VERSION 5.8 ;
BUSBITCHARS "[]" ;
DIVIDERCHAR "/" ;
UNITS
    DATABASE MICRONS 1000 ;
END UNITS

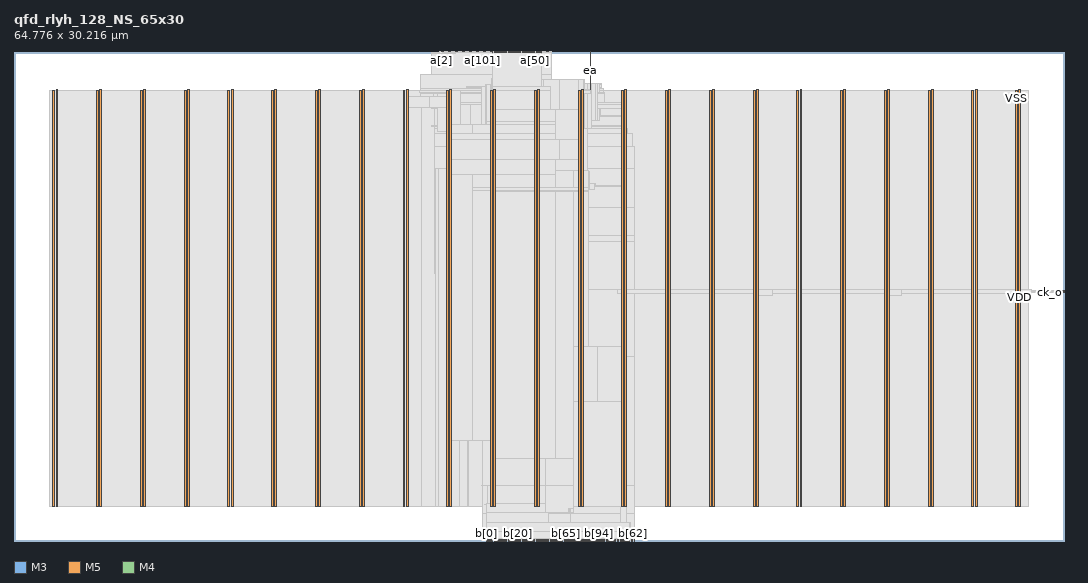
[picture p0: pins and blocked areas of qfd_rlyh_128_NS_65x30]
MACRO qfd_rlyh_128_NS_65x30
  FOREIGN qfd_rlyh_128_NS_65x30 0 0 ;
  CLASS BLOCK ;
  SIZE 64.776 BY 30.216 ;
  PIN a[0]
    DIRECTION INPUT ;
    USE SIGNAL ;
    PORT
      LAYER M3 ;
        RECT  26.244 30.179 26.262 30.216 ;
    END
  END a[0]
  PIN a[100]
    DIRECTION INPUT ;
    USE SIGNAL ;
    PORT
      LAYER M3 ;
        RECT  28.836 30.179 28.854 30.216 ;
    END
  END a[100]
  PIN a[101]
    DIRECTION INPUT ;
    USE SIGNAL ;
    PORT
      LAYER M3 ;
        RECT  28.908 30.179 28.926 30.216 ;
    END
  END a[101]
  PIN a[102]
    DIRECTION INPUT ;
    USE SIGNAL ;
    PORT
      LAYER M3 ;
        RECT  28.98 30.179 28.998 30.216 ;
    END
  END a[102]
  PIN a[103]
    DIRECTION INPUT ;
    USE SIGNAL ;
    PORT
      LAYER M3 ;
        RECT  29.052 30.179 29.07 30.216 ;
    END
  END a[103]
  PIN a[104]
    DIRECTION INPUT ;
    USE SIGNAL ;
    PORT
      LAYER M3 ;
        RECT  29.124 30.179 29.142 30.216 ;
    END
  END a[104]
  PIN a[105]
    DIRECTION INPUT ;
    USE SIGNAL ;
    PORT
      LAYER M3 ;
        RECT  29.196 30.179 29.214 30.216 ;
    END
  END a[105]
  PIN a[106]
    DIRECTION INPUT ;
    USE SIGNAL ;
    PORT
      LAYER M3 ;
        RECT  29.268 30.179 29.286 30.216 ;
    END
  END a[106]
  PIN a[107]
    DIRECTION INPUT ;
    USE SIGNAL ;
    PORT
      LAYER M3 ;
        RECT  29.34 30.179 29.358 30.216 ;
    END
  END a[107]
  PIN a[108]
    DIRECTION INPUT ;
    USE SIGNAL ;
    PORT
      LAYER M3 ;
        RECT  29.412 30.179 29.43 30.216 ;
    END
  END a[108]
  PIN a[109]
    DIRECTION INPUT ;
    USE SIGNAL ;
    PORT
      LAYER M3 ;
        RECT  29.484 30.179 29.502 30.216 ;
    END
  END a[109]
  PIN a[10]
    DIRECTION INPUT ;
    USE SIGNAL ;
    PORT
      LAYER M3 ;
        RECT  26.964 30.179 26.982 30.216 ;
    END
  END a[10]
  PIN a[110]
    DIRECTION INPUT ;
    USE SIGNAL ;
    PORT
      LAYER M3 ;
        RECT  29.556 30.179 29.574 30.216 ;
    END
  END a[110]
  PIN a[111]
    DIRECTION INPUT ;
    USE SIGNAL ;
    PORT
      LAYER M3 ;
        RECT  29.628 30.179 29.646 30.216 ;
    END
  END a[111]
  PIN a[112]
    DIRECTION INPUT ;
    USE SIGNAL ;
    PORT
      LAYER M3 ;
        RECT  29.7 30.179 29.718 30.216 ;
    END
  END a[112]
  PIN a[113]
    DIRECTION INPUT ;
    USE SIGNAL ;
    PORT
      LAYER M3 ;
        RECT  29.772 30.179 29.79 30.216 ;
    END
  END a[113]
  PIN a[114]
    DIRECTION INPUT ;
    USE SIGNAL ;
    PORT
      LAYER M3 ;
        RECT  29.844 30.179 29.862 30.216 ;
    END
  END a[114]
  PIN a[115]
    DIRECTION INPUT ;
    USE SIGNAL ;
    PORT
      LAYER M3 ;
        RECT  29.916 30.179 29.934 30.216 ;
    END
  END a[115]
  PIN a[116]
    DIRECTION INPUT ;
    USE SIGNAL ;
    PORT
      LAYER M3 ;
        RECT  29.988 30.179 30.006 30.216 ;
    END
  END a[116]
  PIN a[117]
    DIRECTION INPUT ;
    USE SIGNAL ;
    PORT
      LAYER M3 ;
        RECT  30.06 30.179 30.078 30.216 ;
    END
  END a[117]
  PIN a[118]
    DIRECTION INPUT ;
    USE SIGNAL ;
    PORT
      LAYER M3 ;
        RECT  30.132 30.179 30.15 30.216 ;
    END
  END a[118]
  PIN a[119]
    DIRECTION INPUT ;
    USE SIGNAL ;
    PORT
      LAYER M3 ;
        RECT  30.204 30.179 30.222 30.216 ;
    END
  END a[119]
  PIN a[11]
    DIRECTION INPUT ;
    USE SIGNAL ;
    PORT
      LAYER M3 ;
        RECT  27.036 30.179 27.054 30.216 ;
    END
  END a[11]
  PIN a[120]
    DIRECTION INPUT ;
    USE SIGNAL ;
    PORT
      LAYER M3 ;
        RECT  30.276 30.179 30.294 30.216 ;
    END
  END a[120]
  PIN a[121]
    DIRECTION INPUT ;
    USE SIGNAL ;
    PORT
      LAYER M3 ;
        RECT  30.348 30.179 30.366 30.216 ;
    END
  END a[121]
  PIN a[122]
    DIRECTION INPUT ;
    USE SIGNAL ;
    PORT
      LAYER M3 ;
        RECT  30.42 30.179 30.438 30.216 ;
    END
  END a[122]
  PIN a[123]
    DIRECTION INPUT ;
    USE SIGNAL ;
    PORT
      LAYER M3 ;
        RECT  30.492 30.179 30.51 30.216 ;
    END
  END a[123]
  PIN a[124]
    DIRECTION INPUT ;
    USE SIGNAL ;
    PORT
      LAYER M3 ;
        RECT  30.564 30.179 30.582 30.216 ;
    END
  END a[124]
  PIN a[125]
    DIRECTION INPUT ;
    USE SIGNAL ;
    PORT
      LAYER M3 ;
        RECT  30.636 30.179 30.654 30.216 ;
    END
  END a[125]
  PIN a[126]
    DIRECTION INPUT ;
    USE SIGNAL ;
    PORT
      LAYER M3 ;
        RECT  30.708 30.179 30.726 30.216 ;
    END
  END a[126]
  PIN a[127]
    DIRECTION INPUT ;
    USE SIGNAL ;
    PORT
      LAYER M3 ;
        RECT  30.78 30.179 30.798 30.216 ;
    END
  END a[127]
  PIN a[12]
    DIRECTION INPUT ;
    USE SIGNAL ;
    PORT
      LAYER M3 ;
        RECT  27.108 30.179 27.126 30.216 ;
    END
  END a[12]
  PIN a[13]
    DIRECTION INPUT ;
    USE SIGNAL ;
    PORT
      LAYER M3 ;
        RECT  27.18 30.179 27.198 30.216 ;
    END
  END a[13]
  PIN a[14]
    DIRECTION INPUT ;
    USE SIGNAL ;
    PORT
      LAYER M3 ;
        RECT  27.252 30.179 27.27 30.216 ;
    END
  END a[14]
  PIN a[15]
    DIRECTION INPUT ;
    USE SIGNAL ;
    PORT
      LAYER M3 ;
        RECT  27.324 30.179 27.342 30.216 ;
    END
  END a[15]
  PIN a[16]
    DIRECTION INPUT ;
    USE SIGNAL ;
    PORT
      LAYER M3 ;
        RECT  27.396 30.179 27.414 30.216 ;
    END
  END a[16]
  PIN a[17]
    DIRECTION INPUT ;
    USE SIGNAL ;
    PORT
      LAYER M3 ;
        RECT  27.468 30.179 27.486 30.216 ;
    END
  END a[17]
  PIN a[18]
    DIRECTION INPUT ;
    USE SIGNAL ;
    PORT
      LAYER M3 ;
        RECT  27.54 30.179 27.558 30.216 ;
    END
  END a[18]
  PIN a[19]
    DIRECTION INPUT ;
    USE SIGNAL ;
    PORT
      LAYER M3 ;
        RECT  27.612 30.179 27.63 30.216 ;
    END
  END a[19]
  PIN a[1]
    DIRECTION INPUT ;
    USE SIGNAL ;
    PORT
      LAYER M3 ;
        RECT  26.316 30.179 26.334 30.216 ;
    END
  END a[1]
  PIN a[20]
    DIRECTION INPUT ;
    USE SIGNAL ;
    PORT
      LAYER M3 ;
        RECT  27.684 30.179 27.702 30.216 ;
    END
  END a[20]
  PIN a[21]
    DIRECTION INPUT ;
    USE SIGNAL ;
    PORT
      LAYER M3 ;
        RECT  27.756 30.179 27.774 30.216 ;
    END
  END a[21]
  PIN a[22]
    DIRECTION INPUT ;
    USE SIGNAL ;
    PORT
      LAYER M3 ;
        RECT  27.828 30.179 27.846 30.216 ;
    END
  END a[22]
  PIN a[23]
    DIRECTION INPUT ;
    USE SIGNAL ;
    PORT
      LAYER M3 ;
        RECT  27.9 30.179 27.918 30.216 ;
    END
  END a[23]
  PIN a[24]
    DIRECTION INPUT ;
    USE SIGNAL ;
    PORT
      LAYER M3 ;
        RECT  27.972 30.179 27.99 30.216 ;
    END
  END a[24]
  PIN a[25]
    DIRECTION INPUT ;
    USE SIGNAL ;
    PORT
      LAYER M3 ;
        RECT  28.044 30.179 28.062 30.216 ;
    END
  END a[25]
  PIN a[26]
    DIRECTION INPUT ;
    USE SIGNAL ;
    PORT
      LAYER M3 ;
        RECT  28.116 30.179 28.134 30.216 ;
    END
  END a[26]
  PIN a[27]
    DIRECTION INPUT ;
    USE SIGNAL ;
    PORT
      LAYER M3 ;
        RECT  28.188 30.179 28.206 30.216 ;
    END
  END a[27]
  PIN a[28]
    DIRECTION INPUT ;
    USE SIGNAL ;
    PORT
      LAYER M3 ;
        RECT  28.26 30.179 28.278 30.216 ;
    END
  END a[28]
  PIN a[29]
    DIRECTION INPUT ;
    USE SIGNAL ;
    PORT
      LAYER M3 ;
        RECT  28.332 30.179 28.35 30.216 ;
    END
  END a[29]
  PIN a[2]
    DIRECTION INPUT ;
    USE SIGNAL ;
    PORT
      LAYER M3 ;
        RECT  26.388 30.179 26.406 30.216 ;
    END
  END a[2]
  PIN a[30]
    DIRECTION INPUT ;
    USE SIGNAL ;
    PORT
      LAYER M3 ;
        RECT  28.404 30.179 28.422 30.216 ;
    END
  END a[30]
  PIN a[31]
    DIRECTION INPUT ;
    USE SIGNAL ;
    PORT
      LAYER M3 ;
        RECT  28.476 30.179 28.494 30.216 ;
    END
  END a[31]
  PIN a[32]
    DIRECTION INPUT ;
    USE SIGNAL ;
    PORT
      LAYER M3 ;
        RECT  30.852 30.179 30.87 30.216 ;
    END
  END a[32]
  PIN a[33]
    DIRECTION INPUT ;
    USE SIGNAL ;
    PORT
      LAYER M3 ;
        RECT  30.924 30.179 30.942 30.216 ;
    END
  END a[33]
  PIN a[34]
    DIRECTION INPUT ;
    USE SIGNAL ;
    PORT
      LAYER M3 ;
        RECT  30.996 30.179 31.014 30.216 ;
    END
  END a[34]
  PIN a[35]
    DIRECTION INPUT ;
    USE SIGNAL ;
    PORT
      LAYER M3 ;
        RECT  31.068 30.179 31.086 30.216 ;
    END
  END a[35]
  PIN a[36]
    DIRECTION INPUT ;
    USE SIGNAL ;
    PORT
      LAYER M3 ;
        RECT  31.14 30.179 31.158 30.216 ;
    END
  END a[36]
  PIN a[37]
    DIRECTION INPUT ;
    USE SIGNAL ;
    PORT
      LAYER M3 ;
        RECT  31.212 30.179 31.23 30.216 ;
    END
  END a[37]
  PIN a[38]
    DIRECTION INPUT ;
    USE SIGNAL ;
    PORT
      LAYER M3 ;
        RECT  31.284 30.179 31.302 30.216 ;
    END
  END a[38]
  PIN a[39]
    DIRECTION INPUT ;
    USE SIGNAL ;
    PORT
      LAYER M3 ;
        RECT  31.356 30.179 31.374 30.216 ;
    END
  END a[39]
  PIN a[3]
    DIRECTION INPUT ;
    USE SIGNAL ;
    PORT
      LAYER M3 ;
        RECT  26.46 30.179 26.478 30.216 ;
    END
  END a[3]
  PIN a[40]
    DIRECTION INPUT ;
    USE SIGNAL ;
    PORT
      LAYER M3 ;
        RECT  31.428 30.179 31.446 30.216 ;
    END
  END a[40]
  PIN a[41]
    DIRECTION INPUT ;
    USE SIGNAL ;
    PORT
      LAYER M3 ;
        RECT  31.5 30.179 31.518 30.216 ;
    END
  END a[41]
  PIN a[42]
    DIRECTION INPUT ;
    USE SIGNAL ;
    PORT
      LAYER M3 ;
        RECT  31.572 30.179 31.59 30.216 ;
    END
  END a[42]
  PIN a[43]
    DIRECTION INPUT ;
    USE SIGNAL ;
    PORT
      LAYER M3 ;
        RECT  31.644 30.179 31.662 30.216 ;
    END
  END a[43]
  PIN a[44]
    DIRECTION INPUT ;
    USE SIGNAL ;
    PORT
      LAYER M3 ;
        RECT  31.716 30.179 31.734 30.216 ;
    END
  END a[44]
  PIN a[45]
    DIRECTION INPUT ;
    USE SIGNAL ;
    PORT
      LAYER M3 ;
        RECT  31.788 30.179 31.806 30.216 ;
    END
  END a[45]
  PIN a[46]
    DIRECTION INPUT ;
    USE SIGNAL ;
    PORT
      LAYER M3 ;
        RECT  31.86 30.179 31.878 30.216 ;
    END
  END a[46]
  PIN a[47]
    DIRECTION INPUT ;
    USE SIGNAL ;
    PORT
      LAYER M3 ;
        RECT  31.932 30.179 31.95 30.216 ;
    END
  END a[47]
  PIN a[48]
    DIRECTION INPUT ;
    USE SIGNAL ;
    PORT
      LAYER M3 ;
        RECT  32.004 30.179 32.022 30.216 ;
    END
  END a[48]
  PIN a[49]
    DIRECTION INPUT ;
    USE SIGNAL ;
    PORT
      LAYER M3 ;
        RECT  32.076 30.179 32.094 30.216 ;
    END
  END a[49]
  PIN a[4]
    DIRECTION INPUT ;
    USE SIGNAL ;
    PORT
      LAYER M3 ;
        RECT  26.532 30.179 26.55 30.216 ;
    END
  END a[4]
  PIN a[50]
    DIRECTION INPUT ;
    USE SIGNAL ;
    PORT
      LAYER M3 ;
        RECT  32.148 30.179 32.166 30.216 ;
    END
  END a[50]
  PIN a[51]
    DIRECTION INPUT ;
    USE SIGNAL ;
    PORT
      LAYER M3 ;
        RECT  32.22 30.179 32.238 30.216 ;
    END
  END a[51]
  PIN a[52]
    DIRECTION INPUT ;
    USE SIGNAL ;
    PORT
      LAYER M3 ;
        RECT  32.292 30.179 32.31 30.216 ;
    END
  END a[52]
  PIN a[53]
    DIRECTION INPUT ;
    USE SIGNAL ;
    PORT
      LAYER M3 ;
        RECT  32.364 30.179 32.382 30.216 ;
    END
  END a[53]
  PIN a[54]
    DIRECTION INPUT ;
    USE SIGNAL ;
    PORT
      LAYER M3 ;
        RECT  32.436 30.179 32.454 30.216 ;
    END
  END a[54]
  PIN a[55]
    DIRECTION INPUT ;
    USE SIGNAL ;
    PORT
      LAYER M3 ;
        RECT  32.508 30.179 32.526 30.216 ;
    END
  END a[55]
  PIN a[56]
    DIRECTION INPUT ;
    USE SIGNAL ;
    PORT
      LAYER M3 ;
        RECT  32.58 30.179 32.598 30.216 ;
    END
  END a[56]
  PIN a[57]
    DIRECTION INPUT ;
    USE SIGNAL ;
    PORT
      LAYER M3 ;
        RECT  32.652 30.179 32.67 30.216 ;
    END
  END a[57]
  PIN a[58]
    DIRECTION INPUT ;
    USE SIGNAL ;
    PORT
      LAYER M3 ;
        RECT  32.724 30.179 32.742 30.216 ;
    END
  END a[58]
  PIN a[59]
    DIRECTION INPUT ;
    USE SIGNAL ;
    PORT
      LAYER M3 ;
        RECT  32.796 30.179 32.814 30.216 ;
    END
  END a[59]
  PIN a[5]
    DIRECTION INPUT ;
    USE SIGNAL ;
    PORT
      LAYER M3 ;
        RECT  26.604 30.179 26.622 30.216 ;
    END
  END a[5]
  PIN a[60]
    DIRECTION INPUT ;
    USE SIGNAL ;
    PORT
      LAYER M3 ;
        RECT  32.868 30.179 32.886 30.216 ;
    END
  END a[60]
  PIN a[61]
    DIRECTION INPUT ;
    USE SIGNAL ;
    PORT
      LAYER M3 ;
        RECT  32.94 30.179 32.958 30.216 ;
    END
  END a[61]
  PIN a[62]
    DIRECTION INPUT ;
    USE SIGNAL ;
    PORT
      LAYER M3 ;
        RECT  33.012 30.179 33.03 30.216 ;
    END
  END a[62]
  PIN a[63]
    DIRECTION INPUT ;
    USE SIGNAL ;
    PORT
      LAYER M3 ;
        RECT  33.084 30.179 33.102 30.216 ;
    END
  END a[63]
  PIN a[64]
    DIRECTION INPUT ;
    USE SIGNAL ;
    PORT
      LAYER M5 ;
        RECT  29.52 30.132 29.544 30.216 ;
    END
  END a[64]
  PIN a[65]
    DIRECTION INPUT ;
    USE SIGNAL ;
    PORT
      LAYER M5 ;
        RECT  29.616 30.132 29.64 30.216 ;
    END
  END a[65]
  PIN a[66]
    DIRECTION INPUT ;
    USE SIGNAL ;
    PORT
      LAYER M5 ;
        RECT  29.712 30.132 29.736 30.216 ;
    END
  END a[66]
  PIN a[67]
    DIRECTION INPUT ;
    USE SIGNAL ;
    PORT
      LAYER M5 ;
        RECT  29.808 30.132 29.832 30.216 ;
    END
  END a[67]
  PIN a[68]
    DIRECTION INPUT ;
    USE SIGNAL ;
    PORT
      LAYER M5 ;
        RECT  29.904 30.132 29.928 30.216 ;
    END
  END a[68]
  PIN a[69]
    DIRECTION INPUT ;
    USE SIGNAL ;
    PORT
      LAYER M5 ;
        RECT  30 30.132 30.024 30.216 ;
    END
  END a[69]
  PIN a[6]
    DIRECTION INPUT ;
    USE SIGNAL ;
    PORT
      LAYER M3 ;
        RECT  26.676 30.179 26.694 30.216 ;
    END
  END a[6]
  PIN a[70]
    DIRECTION INPUT ;
    USE SIGNAL ;
    PORT
      LAYER M5 ;
        RECT  30.096 30.132 30.12 30.216 ;
    END
  END a[70]
  PIN a[71]
    DIRECTION INPUT ;
    USE SIGNAL ;
    PORT
      LAYER M5 ;
        RECT  30.192 30.132 30.216 30.216 ;
    END
  END a[71]
  PIN a[72]
    DIRECTION INPUT ;
    USE SIGNAL ;
    PORT
      LAYER M5 ;
        RECT  30.288 30.132 30.312 30.216 ;
    END
  END a[72]
  PIN a[73]
    DIRECTION INPUT ;
    USE SIGNAL ;
    PORT
      LAYER M5 ;
        RECT  30.384 30.132 30.408 30.216 ;
    END
  END a[73]
  PIN a[74]
    DIRECTION INPUT ;
    USE SIGNAL ;
    PORT
      LAYER M5 ;
        RECT  30.48 30.132 30.504 30.216 ;
    END
  END a[74]
  PIN a[75]
    DIRECTION INPUT ;
    USE SIGNAL ;
    PORT
      LAYER M5 ;
        RECT  30.576 30.132 30.6 30.216 ;
    END
  END a[75]
  PIN a[76]
    DIRECTION INPUT ;
    USE SIGNAL ;
    PORT
      LAYER M5 ;
        RECT  30.672 30.132 30.696 30.216 ;
    END
  END a[76]
  PIN a[77]
    DIRECTION INPUT ;
    USE SIGNAL ;
    PORT
      LAYER M5 ;
        RECT  30.768 30.132 30.792 30.216 ;
    END
  END a[77]
  PIN a[78]
    DIRECTION INPUT ;
    USE SIGNAL ;
    PORT
      LAYER M5 ;
        RECT  30.864 30.132 30.888 30.216 ;
    END
  END a[78]
  PIN a[79]
    DIRECTION INPUT ;
    USE SIGNAL ;
    PORT
      LAYER M5 ;
        RECT  30.96 30.132 30.984 30.216 ;
    END
  END a[79]
  PIN a[7]
    DIRECTION INPUT ;
    USE SIGNAL ;
    PORT
      LAYER M3 ;
        RECT  26.748 30.179 26.766 30.216 ;
    END
  END a[7]
  PIN a[80]
    DIRECTION INPUT ;
    USE SIGNAL ;
    PORT
      LAYER M5 ;
        RECT  31.056 30.132 31.08 30.216 ;
    END
  END a[80]
  PIN a[81]
    DIRECTION INPUT ;
    USE SIGNAL ;
    PORT
      LAYER M5 ;
        RECT  31.152 30.132 31.176 30.216 ;
    END
  END a[81]
  PIN a[82]
    DIRECTION INPUT ;
    USE SIGNAL ;
    PORT
      LAYER M5 ;
        RECT  31.248 30.132 31.272 30.216 ;
    END
  END a[82]
  PIN a[83]
    DIRECTION INPUT ;
    USE SIGNAL ;
    PORT
      LAYER M5 ;
        RECT  31.344 30.132 31.368 30.216 ;
    END
  END a[83]
  PIN a[84]
    DIRECTION INPUT ;
    USE SIGNAL ;
    PORT
      LAYER M5 ;
        RECT  31.44 30.132 31.464 30.216 ;
    END
  END a[84]
  PIN a[85]
    DIRECTION INPUT ;
    USE SIGNAL ;
    PORT
      LAYER M5 ;
        RECT  31.536 30.132 31.56 30.216 ;
    END
  END a[85]
  PIN a[86]
    DIRECTION INPUT ;
    USE SIGNAL ;
    PORT
      LAYER M5 ;
        RECT  31.632 30.132 31.656 30.216 ;
    END
  END a[86]
  PIN a[87]
    DIRECTION INPUT ;
    USE SIGNAL ;
    PORT
      LAYER M5 ;
        RECT  31.728 30.132 31.752 30.216 ;
    END
  END a[87]
  PIN a[88]
    DIRECTION INPUT ;
    USE SIGNAL ;
    PORT
      LAYER M5 ;
        RECT  31.824 30.132 31.848 30.216 ;
    END
  END a[88]
  PIN a[89]
    DIRECTION INPUT ;
    USE SIGNAL ;
    PORT
      LAYER M5 ;
        RECT  31.92 30.132 31.944 30.216 ;
    END
  END a[89]
  PIN a[8]
    DIRECTION INPUT ;
    USE SIGNAL ;
    PORT
      LAYER M3 ;
        RECT  26.82 30.179 26.838 30.216 ;
    END
  END a[8]
  PIN a[90]
    DIRECTION INPUT ;
    USE SIGNAL ;
    PORT
      LAYER M5 ;
        RECT  32.016 30.132 32.04 30.216 ;
    END
  END a[90]
  PIN a[91]
    DIRECTION INPUT ;
    USE SIGNAL ;
    PORT
      LAYER M5 ;
        RECT  32.112 30.132 32.136 30.216 ;
    END
  END a[91]
  PIN a[92]
    DIRECTION INPUT ;
    USE SIGNAL ;
    PORT
      LAYER M5 ;
        RECT  32.208 30.132 32.232 30.216 ;
    END
  END a[92]
  PIN a[93]
    DIRECTION INPUT ;
    USE SIGNAL ;
    PORT
      LAYER M5 ;
        RECT  32.304 30.132 32.328 30.216 ;
    END
  END a[93]
  PIN a[94]
    DIRECTION INPUT ;
    USE SIGNAL ;
    PORT
      LAYER M5 ;
        RECT  32.4 30.132 32.424 30.216 ;
    END
  END a[94]
  PIN a[95]
    DIRECTION INPUT ;
    USE SIGNAL ;
    PORT
      LAYER M5 ;
        RECT  32.496 30.132 32.52 30.216 ;
    END
  END a[95]
  PIN a[96]
    DIRECTION INPUT ;
    USE SIGNAL ;
    PORT
      LAYER M3 ;
        RECT  28.548 30.179 28.566 30.216 ;
    END
  END a[96]
  PIN a[97]
    DIRECTION INPUT ;
    USE SIGNAL ;
    PORT
      LAYER M3 ;
        RECT  28.62 30.179 28.638 30.216 ;
    END
  END a[97]
  PIN a[98]
    DIRECTION INPUT ;
    USE SIGNAL ;
    PORT
      LAYER M3 ;
        RECT  28.692 30.179 28.71 30.216 ;
    END
  END a[98]
  PIN a[99]
    DIRECTION INPUT ;
    USE SIGNAL ;
    PORT
      LAYER M3 ;
        RECT  28.764 30.179 28.782 30.216 ;
    END
  END a[99]
  PIN a[9]
    DIRECTION INPUT ;
    USE SIGNAL ;
    PORT
      LAYER M3 ;
        RECT  26.892 30.179 26.91 30.216 ;
    END
  END a[9]
  PIN b[0]
    DIRECTION OUTPUT ;
    USE SIGNAL ;
    PORT
      LAYER M5 ;
        RECT  29.136 0 29.16 0.084 ;
    END
  END b[0]
  PIN b[100]
    DIRECTION OUTPUT ;
    USE SIGNAL ;
    PORT
      LAYER M5 ;
        RECT  32.592 0 32.616 0.084 ;
    END
  END b[100]
  PIN b[101]
    DIRECTION OUTPUT ;
    USE SIGNAL ;
    PORT
      LAYER M5 ;
        RECT  32.688 0 32.712 0.084 ;
    END
  END b[101]
  PIN b[102]
    DIRECTION OUTPUT ;
    USE SIGNAL ;
    PORT
      LAYER M5 ;
        RECT  32.784 0 32.808 0.084 ;
    END
  END b[102]
  PIN b[103]
    DIRECTION OUTPUT ;
    USE SIGNAL ;
    PORT
      LAYER M5 ;
        RECT  32.88 0 32.904 0.084 ;
    END
  END b[103]
  PIN b[104]
    DIRECTION OUTPUT ;
    USE SIGNAL ;
    PORT
      LAYER M5 ;
        RECT  32.976 0 33 0.084 ;
    END
  END b[104]
  PIN b[105]
    DIRECTION OUTPUT ;
    USE SIGNAL ;
    PORT
      LAYER M5 ;
        RECT  33.072 0 33.096 0.084 ;
    END
  END b[105]
  PIN b[106]
    DIRECTION OUTPUT ;
    USE SIGNAL ;
    PORT
      LAYER M5 ;
        RECT  33.168 0 33.192 0.084 ;
    END
  END b[106]
  PIN b[107]
    DIRECTION OUTPUT ;
    USE SIGNAL ;
    PORT
      LAYER M5 ;
        RECT  33.264 0 33.288 0.084 ;
    END
  END b[107]
  PIN b[108]
    DIRECTION OUTPUT ;
    USE SIGNAL ;
    PORT
      LAYER M5 ;
        RECT  33.36 0 33.384 0.084 ;
    END
  END b[108]
  PIN b[109]
    DIRECTION OUTPUT ;
    USE SIGNAL ;
    PORT
      LAYER M5 ;
        RECT  33.456 0 33.48 0.084 ;
    END
  END b[109]
  PIN b[10]
    DIRECTION OUTPUT ;
    USE SIGNAL ;
    PORT
      LAYER M5 ;
        RECT  30.096 0 30.12 0.084 ;
    END
  END b[10]
  PIN b[110]
    DIRECTION OUTPUT ;
    USE SIGNAL ;
    PORT
      LAYER M5 ;
        RECT  33.552 0 33.576 0.084 ;
    END
  END b[110]
  PIN b[111]
    DIRECTION OUTPUT ;
    USE SIGNAL ;
    PORT
      LAYER M5 ;
        RECT  33.648 0 33.672 0.084 ;
    END
  END b[111]
  PIN b[112]
    DIRECTION OUTPUT ;
    USE SIGNAL ;
    PORT
      LAYER M5 ;
        RECT  33.744 0 33.768 0.084 ;
    END
  END b[112]
  PIN b[113]
    DIRECTION OUTPUT ;
    USE SIGNAL ;
    PORT
      LAYER M5 ;
        RECT  33.84 0 33.864 0.084 ;
    END
  END b[113]
  PIN b[114]
    DIRECTION OUTPUT ;
    USE SIGNAL ;
    PORT
      LAYER M5 ;
        RECT  33.936 0 33.96 0.084 ;
    END
  END b[114]
  PIN b[115]
    DIRECTION OUTPUT ;
    USE SIGNAL ;
    PORT
      LAYER M5 ;
        RECT  34.032 0 34.056 0.084 ;
    END
  END b[115]
  PIN b[116]
    DIRECTION OUTPUT ;
    USE SIGNAL ;
    PORT
      LAYER M5 ;
        RECT  34.128 0 34.152 0.084 ;
    END
  END b[116]
  PIN b[117]
    DIRECTION OUTPUT ;
    USE SIGNAL ;
    PORT
      LAYER M5 ;
        RECT  34.224 0 34.248 0.084 ;
    END
  END b[117]
  PIN b[118]
    DIRECTION OUTPUT ;
    USE SIGNAL ;
    PORT
      LAYER M5 ;
        RECT  34.32 0 34.344 0.084 ;
    END
  END b[118]
  PIN b[119]
    DIRECTION OUTPUT ;
    USE SIGNAL ;
    PORT
      LAYER M5 ;
        RECT  34.416 0 34.44 0.084 ;
    END
  END b[119]
  PIN b[11]
    DIRECTION OUTPUT ;
    USE SIGNAL ;
    PORT
      LAYER M5 ;
        RECT  30.192 0 30.216 0.084 ;
    END
  END b[11]
  PIN b[120]
    DIRECTION OUTPUT ;
    USE SIGNAL ;
    PORT
      LAYER M5 ;
        RECT  34.512 0 34.536 0.084 ;
    END
  END b[120]
  PIN b[121]
    DIRECTION OUTPUT ;
    USE SIGNAL ;
    PORT
      LAYER M5 ;
        RECT  34.608 0 34.632 0.084 ;
    END
  END b[121]
  PIN b[122]
    DIRECTION OUTPUT ;
    USE SIGNAL ;
    PORT
      LAYER M5 ;
        RECT  34.704 0 34.728 0.084 ;
    END
  END b[122]
  PIN b[123]
    DIRECTION OUTPUT ;
    USE SIGNAL ;
    PORT
      LAYER M5 ;
        RECT  34.8 0 34.824 0.084 ;
    END
  END b[123]
  PIN b[124]
    DIRECTION OUTPUT ;
    USE SIGNAL ;
    PORT
      LAYER M5 ;
        RECT  34.896 0 34.92 0.084 ;
    END
  END b[124]
  PIN b[125]
    DIRECTION OUTPUT ;
    USE SIGNAL ;
    PORT
      LAYER M5 ;
        RECT  34.992 0 35.016 0.084 ;
    END
  END b[125]
  PIN b[126]
    DIRECTION OUTPUT ;
    USE SIGNAL ;
    PORT
      LAYER M5 ;
        RECT  35.088 0 35.112 0.084 ;
    END
  END b[126]
  PIN b[127]
    DIRECTION OUTPUT ;
    USE SIGNAL ;
    PORT
      LAYER M5 ;
        RECT  35.184 0 35.208 0.084 ;
    END
  END b[127]
  PIN b[12]
    DIRECTION OUTPUT ;
    USE SIGNAL ;
    PORT
      LAYER M5 ;
        RECT  30.288 0 30.312 0.084 ;
    END
  END b[12]
  PIN b[13]
    DIRECTION OUTPUT ;
    USE SIGNAL ;
    PORT
      LAYER M5 ;
        RECT  30.384 0 30.408 0.084 ;
    END
  END b[13]
  PIN b[14]
    DIRECTION OUTPUT ;
    USE SIGNAL ;
    PORT
      LAYER M5 ;
        RECT  30.48 0 30.504 0.084 ;
    END
  END b[14]
  PIN b[15]
    DIRECTION OUTPUT ;
    USE SIGNAL ;
    PORT
      LAYER M5 ;
        RECT  30.576 0 30.6 0.084 ;
    END
  END b[15]
  PIN b[16]
    DIRECTION OUTPUT ;
    USE SIGNAL ;
    PORT
      LAYER M5 ;
        RECT  30.672 0 30.696 0.084 ;
    END
  END b[16]
  PIN b[17]
    DIRECTION OUTPUT ;
    USE SIGNAL ;
    PORT
      LAYER M5 ;
        RECT  30.768 0 30.792 0.084 ;
    END
  END b[17]
  PIN b[18]
    DIRECTION OUTPUT ;
    USE SIGNAL ;
    PORT
      LAYER M5 ;
        RECT  30.864 0 30.888 0.084 ;
    END
  END b[18]
  PIN b[19]
    DIRECTION OUTPUT ;
    USE SIGNAL ;
    PORT
      LAYER M5 ;
        RECT  30.96 0 30.984 0.084 ;
    END
  END b[19]
  PIN b[1]
    DIRECTION OUTPUT ;
    USE SIGNAL ;
    PORT
      LAYER M5 ;
        RECT  29.232 0 29.256 0.084 ;
    END
  END b[1]
  PIN b[20]
    DIRECTION OUTPUT ;
    USE SIGNAL ;
    PORT
      LAYER M5 ;
        RECT  31.056 0 31.08 0.084 ;
    END
  END b[20]
  PIN b[21]
    DIRECTION OUTPUT ;
    USE SIGNAL ;
    PORT
      LAYER M5 ;
        RECT  31.152 0 31.176 0.084 ;
    END
  END b[21]
  PIN b[22]
    DIRECTION OUTPUT ;
    USE SIGNAL ;
    PORT
      LAYER M5 ;
        RECT  31.248 0 31.272 0.084 ;
    END
  END b[22]
  PIN b[23]
    DIRECTION OUTPUT ;
    USE SIGNAL ;
    PORT
      LAYER M5 ;
        RECT  31.344 0 31.368 0.084 ;
    END
  END b[23]
  PIN b[24]
    DIRECTION OUTPUT ;
    USE SIGNAL ;
    PORT
      LAYER M5 ;
        RECT  31.44 0 31.464 0.084 ;
    END
  END b[24]
  PIN b[25]
    DIRECTION OUTPUT ;
    USE SIGNAL ;
    PORT
      LAYER M5 ;
        RECT  31.536 0 31.56 0.084 ;
    END
  END b[25]
  PIN b[26]
    DIRECTION OUTPUT ;
    USE SIGNAL ;
    PORT
      LAYER M5 ;
        RECT  31.632 0 31.656 0.084 ;
    END
  END b[26]
  PIN b[27]
    DIRECTION OUTPUT ;
    USE SIGNAL ;
    PORT
      LAYER M5 ;
        RECT  31.728 0 31.752 0.084 ;
    END
  END b[27]
  PIN b[28]
    DIRECTION OUTPUT ;
    USE SIGNAL ;
    PORT
      LAYER M5 ;
        RECT  31.824 0 31.848 0.084 ;
    END
  END b[28]
  PIN b[29]
    DIRECTION OUTPUT ;
    USE SIGNAL ;
    PORT
      LAYER M5 ;
        RECT  31.92 0 31.944 0.084 ;
    END
  END b[29]
  PIN b[2]
    DIRECTION OUTPUT ;
    USE SIGNAL ;
    PORT
      LAYER M5 ;
        RECT  29.328 0 29.352 0.084 ;
    END
  END b[2]
  PIN b[30]
    DIRECTION OUTPUT ;
    USE SIGNAL ;
    PORT
      LAYER M5 ;
        RECT  32.016 0 32.04 0.084 ;
    END
  END b[30]
  PIN b[31]
    DIRECTION OUTPUT ;
    USE SIGNAL ;
    PORT
      LAYER M5 ;
        RECT  32.112 0 32.136 0.084 ;
    END
  END b[31]
  PIN b[32]
    DIRECTION OUTPUT ;
    USE SIGNAL ;
    PORT
      LAYER M5 ;
        RECT  35.28 0 35.304 0.084 ;
    END
  END b[32]
  PIN b[33]
    DIRECTION OUTPUT ;
    USE SIGNAL ;
    PORT
      LAYER M5 ;
        RECT  35.376 0 35.4 0.084 ;
    END
  END b[33]
  PIN b[34]
    DIRECTION OUTPUT ;
    USE SIGNAL ;
    PORT
      LAYER M5 ;
        RECT  35.472 0 35.496 0.084 ;
    END
  END b[34]
  PIN b[35]
    DIRECTION OUTPUT ;
    USE SIGNAL ;
    PORT
      LAYER M5 ;
        RECT  35.568 0 35.592 0.084 ;
    END
  END b[35]
  PIN b[36]
    DIRECTION OUTPUT ;
    USE SIGNAL ;
    PORT
      LAYER M5 ;
        RECT  35.664 0 35.688 0.084 ;
    END
  END b[36]
  PIN b[37]
    DIRECTION OUTPUT ;
    USE SIGNAL ;
    PORT
      LAYER M5 ;
        RECT  35.76 0 35.784 0.084 ;
    END
  END b[37]
  PIN b[38]
    DIRECTION OUTPUT ;
    USE SIGNAL ;
    PORT
      LAYER M5 ;
        RECT  35.856 0 35.88 0.084 ;
    END
  END b[38]
  PIN b[39]
    DIRECTION OUTPUT ;
    USE SIGNAL ;
    PORT
      LAYER M5 ;
        RECT  35.952 0 35.976 0.084 ;
    END
  END b[39]
  PIN b[3]
    DIRECTION OUTPUT ;
    USE SIGNAL ;
    PORT
      LAYER M5 ;
        RECT  29.424 0 29.448 0.084 ;
    END
  END b[3]
  PIN b[40]
    DIRECTION OUTPUT ;
    USE SIGNAL ;
    PORT
      LAYER M5 ;
        RECT  36.048 0 36.072 0.084 ;
    END
  END b[40]
  PIN b[41]
    DIRECTION OUTPUT ;
    USE SIGNAL ;
    PORT
      LAYER M5 ;
        RECT  36.144 0 36.168 0.084 ;
    END
  END b[41]
  PIN b[42]
    DIRECTION OUTPUT ;
    USE SIGNAL ;
    PORT
      LAYER M5 ;
        RECT  36.24 0 36.264 0.084 ;
    END
  END b[42]
  PIN b[43]
    DIRECTION OUTPUT ;
    USE SIGNAL ;
    PORT
      LAYER M5 ;
        RECT  36.336 0 36.36 0.084 ;
    END
  END b[43]
  PIN b[44]
    DIRECTION OUTPUT ;
    USE SIGNAL ;
    PORT
      LAYER M5 ;
        RECT  36.432 0 36.456 0.084 ;
    END
  END b[44]
  PIN b[45]
    DIRECTION OUTPUT ;
    USE SIGNAL ;
    PORT
      LAYER M5 ;
        RECT  36.528 0 36.552 0.084 ;
    END
  END b[45]
  PIN b[46]
    DIRECTION OUTPUT ;
    USE SIGNAL ;
    PORT
      LAYER M5 ;
        RECT  36.624 0 36.648 0.084 ;
    END
  END b[46]
  PIN b[47]
    DIRECTION OUTPUT ;
    USE SIGNAL ;
    PORT
      LAYER M5 ;
        RECT  36.72 0 36.744 0.084 ;
    END
  END b[47]
  PIN b[48]
    DIRECTION OUTPUT ;
    USE SIGNAL ;
    PORT
      LAYER M5 ;
        RECT  36.816 0 36.84 0.084 ;
    END
  END b[48]
  PIN b[49]
    DIRECTION OUTPUT ;
    USE SIGNAL ;
    PORT
      LAYER M5 ;
        RECT  36.912 0 36.936 0.084 ;
    END
  END b[49]
  PIN b[4]
    DIRECTION OUTPUT ;
    USE SIGNAL ;
    PORT
      LAYER M5 ;
        RECT  29.52 0 29.544 0.084 ;
    END
  END b[4]
  PIN b[50]
    DIRECTION OUTPUT ;
    USE SIGNAL ;
    PORT
      LAYER M5 ;
        RECT  37.008 0 37.032 0.084 ;
    END
  END b[50]
  PIN b[51]
    DIRECTION OUTPUT ;
    USE SIGNAL ;
    PORT
      LAYER M5 ;
        RECT  37.104 0 37.128 0.084 ;
    END
  END b[51]
  PIN b[52]
    DIRECTION OUTPUT ;
    USE SIGNAL ;
    PORT
      LAYER M5 ;
        RECT  37.2 0 37.224 0.084 ;
    END
  END b[52]
  PIN b[53]
    DIRECTION OUTPUT ;
    USE SIGNAL ;
    PORT
      LAYER M5 ;
        RECT  37.296 0 37.32 0.084 ;
    END
  END b[53]
  PIN b[54]
    DIRECTION OUTPUT ;
    USE SIGNAL ;
    PORT
      LAYER M5 ;
        RECT  37.392 0 37.416 0.084 ;
    END
  END b[54]
  PIN b[55]
    DIRECTION OUTPUT ;
    USE SIGNAL ;
    PORT
      LAYER M5 ;
        RECT  37.488 0 37.512 0.084 ;
    END
  END b[55]
  PIN b[56]
    DIRECTION OUTPUT ;
    USE SIGNAL ;
    PORT
      LAYER M5 ;
        RECT  37.584 0 37.608 0.084 ;
    END
  END b[56]
  PIN b[57]
    DIRECTION OUTPUT ;
    USE SIGNAL ;
    PORT
      LAYER M5 ;
        RECT  37.68 0 37.704 0.084 ;
    END
  END b[57]
  PIN b[58]
    DIRECTION OUTPUT ;
    USE SIGNAL ;
    PORT
      LAYER M5 ;
        RECT  37.776 0 37.8 0.084 ;
    END
  END b[58]
  PIN b[59]
    DIRECTION OUTPUT ;
    USE SIGNAL ;
    PORT
      LAYER M5 ;
        RECT  37.872 0 37.896 0.084 ;
    END
  END b[59]
  PIN b[5]
    DIRECTION OUTPUT ;
    USE SIGNAL ;
    PORT
      LAYER M5 ;
        RECT  29.616 0 29.64 0.084 ;
    END
  END b[5]
  PIN b[60]
    DIRECTION OUTPUT ;
    USE SIGNAL ;
    PORT
      LAYER M5 ;
        RECT  37.968 0 37.992 0.084 ;
    END
  END b[60]
  PIN b[61]
    DIRECTION OUTPUT ;
    USE SIGNAL ;
    PORT
      LAYER M5 ;
        RECT  38.064 0 38.088 0.084 ;
    END
  END b[61]
  PIN b[62]
    DIRECTION OUTPUT ;
    USE SIGNAL ;
    PORT
      LAYER M5 ;
        RECT  38.16 0 38.184 0.084 ;
    END
  END b[62]
  PIN b[63]
    DIRECTION OUTPUT ;
    USE SIGNAL ;
    PORT
      LAYER M5 ;
        RECT  38.256 0 38.28 0.084 ;
    END
  END b[63]
  PIN b[64]
    DIRECTION OUTPUT ;
    USE SIGNAL ;
    PORT
      LAYER M3 ;
        RECT  33.948 0 33.966 0.037 ;
    END
  END b[64]
  PIN b[65]
    DIRECTION OUTPUT ;
    USE SIGNAL ;
    PORT
      LAYER M3 ;
        RECT  34.02 0 34.038 0.037 ;
    END
  END b[65]
  PIN b[66]
    DIRECTION OUTPUT ;
    USE SIGNAL ;
    PORT
      LAYER M3 ;
        RECT  34.092 0 34.11 0.037 ;
    END
  END b[66]
  PIN b[67]
    DIRECTION OUTPUT ;
    USE SIGNAL ;
    PORT
      LAYER M3 ;
        RECT  34.164 0 34.182 0.037 ;
    END
  END b[67]
  PIN b[68]
    DIRECTION OUTPUT ;
    USE SIGNAL ;
    PORT
      LAYER M3 ;
        RECT  34.236 0 34.254 0.037 ;
    END
  END b[68]
  PIN b[69]
    DIRECTION OUTPUT ;
    USE SIGNAL ;
    PORT
      LAYER M3 ;
        RECT  34.308 0 34.326 0.037 ;
    END
  END b[69]
  PIN b[6]
    DIRECTION OUTPUT ;
    USE SIGNAL ;
    PORT
      LAYER M5 ;
        RECT  29.712 0 29.736 0.084 ;
    END
  END b[6]
  PIN b[70]
    DIRECTION OUTPUT ;
    USE SIGNAL ;
    PORT
      LAYER M3 ;
        RECT  34.38 0 34.398 0.037 ;
    END
  END b[70]
  PIN b[71]
    DIRECTION OUTPUT ;
    USE SIGNAL ;
    PORT
      LAYER M3 ;
        RECT  34.452 0 34.47 0.037 ;
    END
  END b[71]
  PIN b[72]
    DIRECTION OUTPUT ;
    USE SIGNAL ;
    PORT
      LAYER M3 ;
        RECT  34.524 0 34.542 0.037 ;
    END
  END b[72]
  PIN b[73]
    DIRECTION OUTPUT ;
    USE SIGNAL ;
    PORT
      LAYER M3 ;
        RECT  34.596 0 34.614 0.037 ;
    END
  END b[73]
  PIN b[74]
    DIRECTION OUTPUT ;
    USE SIGNAL ;
    PORT
      LAYER M3 ;
        RECT  34.668 0 34.686 0.037 ;
    END
  END b[74]
  PIN b[75]
    DIRECTION OUTPUT ;
    USE SIGNAL ;
    PORT
      LAYER M3 ;
        RECT  34.74 0 34.758 0.037 ;
    END
  END b[75]
  PIN b[76]
    DIRECTION OUTPUT ;
    USE SIGNAL ;
    PORT
      LAYER M3 ;
        RECT  34.812 0 34.83 0.037 ;
    END
  END b[76]
  PIN b[77]
    DIRECTION OUTPUT ;
    USE SIGNAL ;
    PORT
      LAYER M3 ;
        RECT  34.884 0 34.902 0.037 ;
    END
  END b[77]
  PIN b[78]
    DIRECTION OUTPUT ;
    USE SIGNAL ;
    PORT
      LAYER M3 ;
        RECT  34.956 0 34.974 0.037 ;
    END
  END b[78]
  PIN b[79]
    DIRECTION OUTPUT ;
    USE SIGNAL ;
    PORT
      LAYER M3 ;
        RECT  35.028 0 35.046 0.037 ;
    END
  END b[79]
  PIN b[7]
    DIRECTION OUTPUT ;
    USE SIGNAL ;
    PORT
      LAYER M5 ;
        RECT  29.808 0 29.832 0.084 ;
    END
  END b[7]
  PIN b[80]
    DIRECTION OUTPUT ;
    USE SIGNAL ;
    PORT
      LAYER M3 ;
        RECT  35.1 0 35.118 0.037 ;
    END
  END b[80]
  PIN b[81]
    DIRECTION OUTPUT ;
    USE SIGNAL ;
    PORT
      LAYER M3 ;
        RECT  35.172 0 35.19 0.037 ;
    END
  END b[81]
  PIN b[82]
    DIRECTION OUTPUT ;
    USE SIGNAL ;
    PORT
      LAYER M3 ;
        RECT  35.244 0 35.262 0.037 ;
    END
  END b[82]
  PIN b[83]
    DIRECTION OUTPUT ;
    USE SIGNAL ;
    PORT
      LAYER M3 ;
        RECT  35.316 0 35.334 0.037 ;
    END
  END b[83]
  PIN b[84]
    DIRECTION OUTPUT ;
    USE SIGNAL ;
    PORT
      LAYER M3 ;
        RECT  35.388 0 35.406 0.037 ;
    END
  END b[84]
  PIN b[85]
    DIRECTION OUTPUT ;
    USE SIGNAL ;
    PORT
      LAYER M3 ;
        RECT  35.46 0 35.478 0.037 ;
    END
  END b[85]
  PIN b[86]
    DIRECTION OUTPUT ;
    USE SIGNAL ;
    PORT
      LAYER M3 ;
        RECT  35.532 0 35.55 0.037 ;
    END
  END b[86]
  PIN b[87]
    DIRECTION OUTPUT ;
    USE SIGNAL ;
    PORT
      LAYER M3 ;
        RECT  35.604 0 35.622 0.037 ;
    END
  END b[87]
  PIN b[88]
    DIRECTION OUTPUT ;
    USE SIGNAL ;
    PORT
      LAYER M3 ;
        RECT  35.676 0 35.694 0.037 ;
    END
  END b[88]
  PIN b[89]
    DIRECTION OUTPUT ;
    USE SIGNAL ;
    PORT
      LAYER M3 ;
        RECT  35.748 0 35.766 0.037 ;
    END
  END b[89]
  PIN b[8]
    DIRECTION OUTPUT ;
    USE SIGNAL ;
    PORT
      LAYER M5 ;
        RECT  29.904 0 29.928 0.084 ;
    END
  END b[8]
  PIN b[90]
    DIRECTION OUTPUT ;
    USE SIGNAL ;
    PORT
      LAYER M3 ;
        RECT  35.82 0 35.838 0.037 ;
    END
  END b[90]
  PIN b[91]
    DIRECTION OUTPUT ;
    USE SIGNAL ;
    PORT
      LAYER M3 ;
        RECT  35.892 0 35.91 0.037 ;
    END
  END b[91]
  PIN b[92]
    DIRECTION OUTPUT ;
    USE SIGNAL ;
    PORT
      LAYER M3 ;
        RECT  35.964 0 35.982 0.037 ;
    END
  END b[92]
  PIN b[93]
    DIRECTION OUTPUT ;
    USE SIGNAL ;
    PORT
      LAYER M3 ;
        RECT  36.036 0 36.054 0.037 ;
    END
  END b[93]
  PIN b[94]
    DIRECTION OUTPUT ;
    USE SIGNAL ;
    PORT
      LAYER M3 ;
        RECT  36.108 0 36.126 0.037 ;
    END
  END b[94]
  PIN b[95]
    DIRECTION OUTPUT ;
    USE SIGNAL ;
    PORT
      LAYER M3 ;
        RECT  36.18 0 36.198 0.037 ;
    END
  END b[95]
  PIN b[96]
    DIRECTION OUTPUT ;
    USE SIGNAL ;
    PORT
      LAYER M5 ;
        RECT  32.208 0 32.232 0.084 ;
    END
  END b[96]
  PIN b[97]
    DIRECTION OUTPUT ;
    USE SIGNAL ;
    PORT
      LAYER M5 ;
        RECT  32.304 0 32.328 0.084 ;
    END
  END b[97]
  PIN b[98]
    DIRECTION OUTPUT ;
    USE SIGNAL ;
    PORT
      LAYER M5 ;
        RECT  32.4 0 32.424 0.084 ;
    END
  END b[98]
  PIN b[99]
    DIRECTION OUTPUT ;
    USE SIGNAL ;
    PORT
      LAYER M5 ;
        RECT  32.496 0 32.52 0.084 ;
    END
  END b[99]
  PIN b[9]
    DIRECTION OUTPUT ;
    USE SIGNAL ;
    PORT
      LAYER M5 ;
        RECT  30 0 30.024 0.084 ;
    END
  END b[9]
  PIN ck_o
    DIRECTION OUTPUT ;
    USE SIGNAL ;
    PORT
      LAYER M4 ;
        RECT  64.692 15.312 64.776 15.336 ;
    END
  END ck_o
  PIN ckf
    DIRECTION INPUT ;
    USE SIGNAL ;
    PORT
      LAYER M4 ;
        RECT  64.692 15.408 64.776 15.432 ;
    END
  END ckf
  PIN ea
    DIRECTION INPUT ;
    USE SIGNAL ;
    PORT
      LAYER M5 ;
        RECT  35.568 30.132 35.592 30.216 ;
    END
    PORT
      LAYER M5 ;
        RECT  35.568 27.833 35.592 30.16 ;
    END
  END ea
  PIN eb
    DIRECTION OUTPUT ;
    USE SIGNAL ;
    PORT
      LAYER M3 ;
        RECT  36.252 0 36.27 0.037 ;
    END
  END eb
  PIN VDD
    DIRECTION INOUT ;
    USE POWER ;
    PORT
      LAYER M5 ;
        RECT  61.992 2.151 62.112 27.833 ;
        RECT  59.292 2.151 59.412 27.833 ;
        RECT  56.592 2.151 56.712 27.833 ;
        RECT  53.892 2.151 54.012 27.833 ;
        RECT  51.192 2.151 51.312 27.833 ;
        RECT  48.492 2.151 48.612 27.833 ;
        RECT  45.792 2.151 45.912 27.833 ;
        RECT  43.092 2.151 43.212 27.833 ;
        RECT  40.392 2.151 40.512 27.833 ;
        RECT  37.692 2.151 37.812 27.833 ;
        RECT  34.992 2.151 35.112 27.833 ;
        RECT  32.292 2.151 32.412 27.833 ;
        RECT  29.592 2.151 29.712 27.833 ;
        RECT  26.892 2.151 27.012 27.833 ;
        RECT  24.192 2.151 24.312 27.833 ;
        RECT  21.492 2.151 21.612 27.833 ;
        RECT  18.792 2.151 18.912 27.833 ;
        RECT  16.092 2.151 16.212 27.833 ;
        RECT  13.392 2.151 13.512 27.833 ;
        RECT  10.692 2.151 10.812 27.833 ;
        RECT  7.992 2.151 8.112 27.833 ;
        RECT  5.292 2.151 5.412 27.833 ;
        RECT  2.592 2.151 2.712 27.833 ;
    END
  END VDD
  PIN VSS
    DIRECTION INOUT ;
    USE GROUND ;
    PORT
      LAYER M5 ;
        RECT  61.8 2.137 61.92 27.819 ;
        RECT  59.1 2.137 59.22 27.819 ;
        RECT  56.4 2.137 56.52 27.819 ;
        RECT  53.7 2.137 53.82 27.819 ;
        RECT  51 2.137 51.12 27.819 ;
        RECT  48.3 2.137 48.42 27.819 ;
        RECT  45.6 2.137 45.72 27.819 ;
        RECT  42.9 2.137 43.02 27.819 ;
        RECT  40.2 2.137 40.32 27.819 ;
        RECT  37.5 2.137 37.62 27.819 ;
        RECT  34.8 2.137 34.92 27.819 ;
        RECT  32.1 2.137 32.22 27.819 ;
        RECT  29.4 2.137 29.52 27.819 ;
        RECT  26.7 2.137 26.82 27.819 ;
        RECT  24 2.137 24.12 27.819 ;
        RECT  21.3 2.137 21.42 27.819 ;
        RECT  18.6 2.137 18.72 27.819 ;
        RECT  15.9 2.137 16.02 27.819 ;
        RECT  13.2 2.137 13.32 27.819 ;
        RECT  10.5 2.137 10.62 27.819 ;
        RECT  7.8 2.137 7.92 27.819 ;
        RECT  5.1 2.137 5.22 27.819 ;
        RECT  2.4 2.137 2.52 27.819 ;
    END
  END VSS
  # OT_OBS_CLOSED layer=M5 d_um=1.536 added=15
  OBS
    LAYER RVTN ;
     RECT  2.16 2.16 62.586 2.295 ;
     RECT  2.16 2.565 62.586 2.835 ;
     RECT  2.16 3.105 62.586 3.375 ;
     RECT  2.16 3.645 62.586 3.915 ;
     RECT  2.16 4.185 62.586 4.455 ;
     RECT  2.16 4.725 62.586 4.995 ;
     RECT  2.16 5.265 62.586 5.535 ;
     RECT  2.16 5.805 62.586 6.075 ;
     RECT  2.16 6.345 62.586 6.615 ;
     RECT  2.16 6.885 62.586 7.155 ;
     RECT  2.16 7.425 62.586 7.695 ;
     RECT  2.16 7.965 62.586 8.235 ;
     RECT  2.16 8.505 62.586 8.775 ;
     RECT  2.16 9.045 62.586 9.315 ;
     RECT  2.16 9.585 62.586 9.855 ;
     RECT  2.16 10.125 62.586 10.395 ;
     RECT  2.16 10.665 62.586 10.935 ;
     RECT  2.16 11.205 62.586 11.475 ;
     RECT  2.16 11.745 62.586 12.015 ;
     RECT  2.16 12.285 62.586 12.555 ;
     RECT  2.16 12.825 62.586 13.095 ;
     RECT  2.16 13.365 62.586 13.635 ;
     RECT  2.16 13.905 62.586 14.175 ;
     RECT  2.16 14.445 62.586 14.715 ;
     RECT  2.16 14.985 62.586 15.255 ;
     RECT  2.16 15.525 62.586 15.795 ;
     RECT  2.16 16.065 62.586 16.335 ;
     RECT  2.16 16.605 62.586 16.875 ;
     RECT  2.16 17.145 62.586 17.415 ;
     RECT  2.16 17.685 62.586 17.955 ;
     RECT  2.16 18.225 62.586 18.495 ;
     RECT  2.16 18.765 62.586 19.035 ;
     RECT  2.16 19.305 62.586 19.575 ;
     RECT  2.16 19.845 62.586 20.115 ;
     RECT  2.16 20.385 62.586 20.655 ;
     RECT  2.16 20.925 62.586 21.195 ;
     RECT  2.16 21.465 62.586 21.735 ;
     RECT  2.16 22.005 62.586 22.275 ;
     RECT  2.16 22.545 62.586 22.815 ;
     RECT  2.16 23.085 62.586 23.355 ;
     RECT  2.16 23.625 62.586 23.895 ;
     RECT  2.16 24.165 62.586 24.435 ;
     RECT  2.16 24.705 62.586 24.975 ;
     RECT  2.16 25.245 62.586 25.515 ;
     RECT  2.16 25.785 62.586 26.055 ;
     RECT  2.16 26.325 62.586 26.595 ;
     RECT  2.16 26.865 62.586 27.135 ;
     RECT  2.16 27.405 62.586 27.675 ;
    LAYER RVTP ;
     RECT  2.16 2.295 62.586 2.565 ;
     RECT  2.16 2.835 62.586 3.105 ;
     RECT  2.16 3.375 62.586 3.645 ;
     RECT  2.16 3.915 62.586 4.185 ;
     RECT  2.16 4.455 62.586 4.725 ;
     RECT  2.16 4.995 62.586 5.265 ;
     RECT  2.16 5.535 62.586 5.805 ;
     RECT  2.16 6.075 62.586 6.345 ;
     RECT  2.16 6.615 62.586 6.885 ;
     RECT  2.16 7.155 62.586 7.425 ;
     RECT  2.16 7.695 62.586 7.965 ;
     RECT  2.16 8.235 62.586 8.505 ;
     RECT  2.16 8.775 62.586 9.045 ;
     RECT  2.16 9.315 62.586 9.585 ;
     RECT  2.16 9.855 62.586 10.125 ;
     RECT  2.16 10.395 62.586 10.665 ;
     RECT  2.16 10.935 62.586 11.205 ;
     RECT  2.16 11.475 62.586 11.745 ;
     RECT  2.16 12.015 62.586 12.285 ;
     RECT  2.16 12.555 62.586 12.825 ;
     RECT  2.16 13.095 62.586 13.365 ;
     RECT  2.16 13.635 62.586 13.905 ;
     RECT  2.16 14.175 62.586 14.445 ;
     RECT  2.16 14.715 62.586 14.985 ;
     RECT  2.16 15.255 62.586 15.525 ;
     RECT  2.16 15.795 62.586 16.065 ;
     RECT  2.16 16.335 62.586 16.605 ;
     RECT  2.16 16.875 62.586 17.145 ;
     RECT  2.16 17.415 62.586 17.685 ;
     RECT  2.16 17.955 62.586 18.225 ;
     RECT  2.16 18.495 62.586 18.765 ;
     RECT  2.16 19.035 62.586 19.305 ;
     RECT  2.16 19.575 62.586 19.845 ;
     RECT  2.16 20.115 62.586 20.385 ;
     RECT  2.16 20.655 62.586 20.925 ;
     RECT  2.16 21.195 62.586 21.465 ;
     RECT  2.16 21.735 62.586 22.005 ;
     RECT  2.16 22.275 62.586 22.545 ;
     RECT  2.16 22.815 62.586 23.085 ;
     RECT  2.16 23.355 62.586 23.625 ;
     RECT  2.16 23.895 62.586 24.165 ;
     RECT  2.16 24.435 62.586 24.705 ;
     RECT  2.16 24.975 62.586 25.245 ;
     RECT  2.16 25.515 62.586 25.785 ;
     RECT  2.16 26.055 62.586 26.325 ;
     RECT  2.16 26.595 62.586 26.865 ;
     RECT  2.16 27.135 62.586 27.405 ;
     RECT  2.16 27.675 62.586 27.81 ;
    LAYER M1 ;
     RECT  2.16 2.151 62.586 27.819 ;
    LAYER M2 ;
     RECT  2.16 2.151 25.123 27.819 ;
     RECT  25.123 2.151 25.987 27.936 ;
     RECT  25.087 28.764 25.987 28.782 ;
     RECT  25.987 2.151 26.167 28.782 ;
     RECT  26.311 29.961 26.411 29.979 ;
     RECT  26.419 30.042 26.635 30.06 ;
     RECT  26.635 30.042 26.699 30.168 ;
     RECT  26.167 2.151 27.491 29.052 ;
     RECT  26.699 30.078 27.607 30.168 ;
     RECT  27.491 28.764 27.715 29.052 ;
     RECT  27.607 30.006 27.715 30.168 ;
     RECT  27.491 2.151 27.995 27.936 ;
     RECT  27.995 2.151 28.067 27.9 ;
     RECT  27.715 28.764 28.211 30.168 ;
     RECT  28.211 29.61 28.643 30.168 ;
     RECT  28.643 29.916 29.003 30.168 ;
     RECT  28.211 28.764 29.147 28.782 ;
     RECT  28.067 2.151 29.435 27.864 ;
     RECT  29.003 29.961 30.055 30.168 ;
     RECT  30.055 29.61 30.559 30.168 ;
     RECT  30.559 28.962 30.731 30.168 ;
     RECT  30.731 29.034 30.911 30.168 ;
     RECT  30.911 29.034 31.199 29.052 ;
     RECT  30.911 30.078 31.711 30.168 ;
     RECT  31.711 30.006 31.811 30.168 ;
     RECT  31.927 28.881 32.027 28.899 ;
     RECT  32.035 28.926 32.071 28.944 ;
     RECT  32.071 28.926 32.171 29.052 ;
     RECT  29.435 2.151 32.179 27.819 ;
     RECT  32.171 28.926 32.315 28.944 ;
     RECT  31.811 30.078 32.459 30.168 ;
     RECT  32.179 2.151 32.503 27.864 ;
     RECT  32.503 2.106 32.539 27.864 ;
     RECT  32.459 30.15 33.179 30.168 ;
     RECT  32.539 2.106 33.359 27.936 ;
     RECT  33.727 0.108 33.835 0.126 ;
     RECT  33.835 0.036 34.267 0.126 ;
     RECT  34.267 0.036 34.339 0.279 ;
     RECT  33.359 2.151 34.807 27.936 ;
     RECT  34.339 0.036 34.907 0.594 ;
     RECT  34.807 2.07 34.979 27.936 ;
     RECT  34.907 0.036 35.231 0.324 ;
     RECT  35.231 0.036 35.995 0.054 ;
     RECT  35.995 0.036 36.059 0.09 ;
     RECT  36.059 0.036 36.311 0.054 ;
     RECT  34.979 2.151 36.347 27.936 ;
     RECT  36.347 2.151 62.586 27.819 ;
    LAYER M3 ;
     RECT  33.966 0.012 34.02 0.031 ;
     RECT  34.038 0.012 34.092 0.031 ;
     RECT  34.11 0.012 34.164 0.031 ;
     RECT  34.182 0.012 34.236 0.031 ;
     RECT  34.254 0.012 34.308 0.031 ;
     RECT  34.326 0.012 34.38 0.031 ;
     RECT  34.398 0.012 34.452 0.031 ;
     RECT  34.47 0.012 34.524 0.031 ;
     RECT  34.542 0.012 34.596 0.031 ;
     RECT  34.614 0.012 34.668 0.031 ;
     RECT  34.686 0.012 34.74 0.031 ;
     RECT  34.758 0.012 34.812 0.031 ;
     RECT  34.83 0.012 34.884 0.031 ;
     RECT  34.902 0.012 34.956 0.031 ;
     RECT  34.974 0.012 35.028 0.031 ;
     RECT  35.046 0.012 35.1 0.031 ;
     RECT  35.118 0.012 35.172 0.031 ;
     RECT  35.19 0.012 35.244 0.031 ;
     RECT  35.262 0.012 35.316 0.031 ;
     RECT  35.334 0.012 35.388 0.031 ;
     RECT  35.406 0.012 35.46 0.031 ;
     RECT  35.478 0.012 35.532 0.031 ;
     RECT  35.55 0.012 35.604 0.031 ;
     RECT  35.622 0.012 35.676 0.031 ;
     RECT  35.694 0.012 35.748 0.031 ;
     RECT  35.766 0.012 35.82 0.031 ;
     RECT  35.838 0.012 35.892 0.031 ;
     RECT  35.91 0.012 35.964 0.031 ;
     RECT  35.982 0.012 36.036 0.031 ;
     RECT  36.054 0.012 36.108 0.031 ;
     RECT  36.126 0.012 36.18 0.031 ;
     RECT  36.198 0.012 36.252 0.031 ;
     RECT  33.84 0.031 33.948 0.037 ;
     RECT  33.966 0.031 34.02 0.037 ;
     RECT  34.038 0.031 34.092 0.037 ;
     RECT  34.11 0.031 34.164 0.037 ;
     RECT  34.182 0.031 34.236 0.037 ;
     RECT  34.254 0.031 34.308 0.037 ;
     RECT  34.326 0.031 34.38 0.037 ;
     RECT  34.398 0.031 34.452 0.037 ;
     RECT  34.47 0.031 34.524 0.037 ;
     RECT  34.542 0.031 34.596 0.037 ;
     RECT  34.614 0.031 34.668 0.037 ;
     RECT  34.686 0.031 34.74 0.037 ;
     RECT  34.758 0.031 34.812 0.037 ;
     RECT  34.83 0.031 34.884 0.037 ;
     RECT  34.902 0.031 34.956 0.037 ;
     RECT  34.974 0.031 35.028 0.037 ;
     RECT  35.046 0.031 35.1 0.037 ;
     RECT  35.118 0.031 35.172 0.037 ;
     RECT  35.19 0.031 35.244 0.037 ;
     RECT  35.262 0.031 35.316 0.037 ;
     RECT  35.334 0.031 35.388 0.037 ;
     RECT  35.406 0.031 35.46 0.037 ;
     RECT  35.478 0.031 35.532 0.037 ;
     RECT  35.55 0.031 35.604 0.037 ;
     RECT  35.622 0.031 35.676 0.037 ;
     RECT  35.694 0.031 35.748 0.037 ;
     RECT  35.766 0.031 35.82 0.037 ;
     RECT  35.838 0.031 35.892 0.037 ;
     RECT  35.91 0.031 35.964 0.037 ;
     RECT  35.982 0.031 36.036 0.037 ;
     RECT  36.054 0.031 36.108 0.037 ;
     RECT  36.126 0.031 36.18 0.037 ;
     RECT  36.198 0.031 36.252 0.037 ;
     RECT  36.27 0.031 36.306 0.037 ;
     RECT  33.84 0.037 36.306 0.043 ;
     RECT  30.492 0.043 30.51 0.091 ;
     RECT  30.276 0.091 30.51 0.139 ;
     RECT  29.232 0.187 29.25 0.283 ;
     RECT  31.536 0.139 31.554 0.283 ;
     RECT  29.232 0.283 29.286 0.331 ;
     RECT  32.76 0.235 32.778 0.331 ;
     RECT  37.872 0.091 38.286 0.331 ;
     RECT  29.232 0.331 29.358 0.379 ;
     RECT  31.536 0.283 31.734 0.379 ;
     RECT  32.58 0.331 32.778 0.379 ;
     RECT  33.552 0.043 36.306 0.379 ;
     RECT  37.44 0.331 38.286 0.379 ;
     RECT  28.98 0.379 29.358 0.427 ;
     RECT  30.276 0.139 30.798 0.427 ;
     RECT  31.536 0.379 32.778 0.427 ;
     RECT  28.98 0.427 29.394 0.475 ;
     RECT  30.276 0.427 32.778 0.475 ;
     RECT  33.516 0.379 38.286 0.475 ;
     RECT  28.908 0.475 29.394 1.675 ;
     RECT  30.132 0.475 38.286 1.675 ;
     RECT  2.415 2.143 2.505 2.413 ;
     RECT  5.115 2.143 5.205 2.413 ;
     RECT  7.815 2.143 7.905 2.413 ;
     RECT  10.515 2.143 10.605 2.413 ;
     RECT  13.215 2.143 13.305 2.413 ;
     RECT  15.915 2.143 16.005 2.413 ;
     RECT  18.615 2.143 18.705 2.413 ;
     RECT  21.315 2.143 21.405 2.413 ;
     RECT  24.015 2.143 24.105 2.413 ;
     RECT  26.715 2.143 26.805 2.413 ;
     RECT  40.215 2.143 40.305 2.413 ;
     RECT  42.915 2.143 43.005 2.413 ;
     RECT  45.615 2.143 45.705 2.413 ;
     RECT  48.315 2.143 48.405 2.413 ;
     RECT  51.015 2.143 51.105 2.413 ;
     RECT  53.715 2.143 53.805 2.413 ;
     RECT  56.415 2.143 56.505 2.413 ;
     RECT  59.115 2.143 59.205 2.413 ;
     RECT  61.815 2.143 61.905 2.413 ;
     RECT  28.908 1.675 38.286 3.403 ;
     RECT  27.972 2.263 27.99 10.201 ;
     RECT  27.864 10.201 27.99 11.371 ;
     RECT  28.872 3.403 38.286 11.371 ;
     RECT  61.815 2.413 62.097 15.151 ;
     RECT  61.815 15.151 62.334 15.163 ;
     RECT  46.764 15.163 46.782 15.293 ;
     RECT  54.72 15.163 54.738 15.293 ;
     RECT  61.815 15.163 62.73 15.533 ;
     RECT  27.864 11.371 38.286 18.499 ;
     RECT  26.715 2.413 26.997 18.841 ;
     RECT  27.756 18.499 38.286 18.841 ;
     RECT  26.715 18.841 38.286 20.551 ;
     RECT  25.92 16.501 25.938 22.981 ;
     RECT  26.676 20.551 38.286 22.981 ;
     RECT  25.92 22.981 38.286 24.359 ;
     RECT  25.92 24.359 38.178 25.169 ;
     RECT  25.92 25.169 37.854 25.439 ;
     RECT  25.92 25.439 37.797 25.555 ;
     RECT  25.74 25.555 37.797 25.661 ;
     RECT  25.92 25.661 37.797 26.671 ;
     RECT  24.015 2.413 24.297 26.779 ;
     RECT  24.015 26.779 25.002 26.825 ;
     RECT  25.74 26.671 37.797 26.941 ;
     RECT  25.092 26.941 37.797 27.059 ;
     RECT  2.415 2.413 2.697 27.557 ;
     RECT  5.115 2.413 5.397 27.557 ;
     RECT  7.815 2.413 8.097 27.557 ;
     RECT  10.515 2.413 10.797 27.557 ;
     RECT  13.215 2.413 13.497 27.557 ;
     RECT  15.915 2.413 16.197 27.557 ;
     RECT  18.615 2.413 18.897 27.557 ;
     RECT  21.315 2.413 21.597 27.557 ;
     RECT  24.015 26.825 24.297 27.557 ;
     RECT  37.515 27.059 37.797 27.557 ;
     RECT  40.215 2.413 40.497 27.557 ;
     RECT  42.915 2.413 43.197 27.557 ;
     RECT  45.615 2.413 45.897 27.557 ;
     RECT  48.315 2.413 48.597 27.557 ;
     RECT  51.015 2.413 51.297 27.557 ;
     RECT  53.715 2.413 53.997 27.557 ;
     RECT  56.415 2.413 56.697 27.557 ;
     RECT  59.115 2.413 59.397 27.557 ;
     RECT  61.815 15.533 62.097 27.557 ;
     RECT  25.092 27.059 36.45 27.599 ;
     RECT  34.308 27.599 36.45 27.635 ;
     RECT  25.092 27.599 33.57 27.671 ;
     RECT  34.56 27.635 36.45 27.671 ;
     RECT  25.092 27.671 33.426 27.679 ;
     RECT  25.02 27.679 33.426 27.779 ;
     RECT  34.56 27.671 36.342 27.779 ;
     RECT  2.607 27.557 2.697 27.827 ;
     RECT  5.307 27.557 5.397 27.827 ;
     RECT  8.007 27.557 8.097 27.827 ;
     RECT  10.707 27.557 10.797 27.827 ;
     RECT  13.407 27.557 13.497 27.827 ;
     RECT  16.107 27.557 16.197 27.827 ;
     RECT  18.807 27.557 18.897 27.827 ;
     RECT  21.507 27.557 21.597 27.827 ;
     RECT  24.207 27.557 24.297 27.827 ;
     RECT  37.707 27.557 37.797 27.827 ;
     RECT  40.407 27.557 40.497 27.827 ;
     RECT  43.107 27.557 43.197 27.827 ;
     RECT  45.807 27.557 45.897 27.827 ;
     RECT  48.507 27.557 48.597 27.827 ;
     RECT  51.207 27.557 51.297 27.827 ;
     RECT  53.907 27.557 53.997 27.827 ;
     RECT  56.607 27.557 56.697 27.827 ;
     RECT  59.307 27.557 59.397 27.827 ;
     RECT  62.007 27.557 62.097 27.827 ;
     RECT  25.092 27.779 33.426 27.905 ;
     RECT  34.668 27.779 36.342 27.917 ;
     RECT  34.74 27.917 36.342 27.941 ;
     RECT  34.74 27.941 36.234 27.965 ;
     RECT  34.956 27.965 36.234 28.205 ;
     RECT  34.956 28.205 35.874 28.253 ;
     RECT  34.956 28.253 35.19 28.349 ;
     RECT  35.172 28.349 35.19 28.493 ;
     RECT  25.092 27.905 33.174 28.787 ;
     RECT  25.776 28.787 33.174 30.125 ;
     RECT  26.244 30.125 33.174 30.173 ;
     RECT  26.244 30.173 33.102 30.179 ;
     RECT  26.262 30.179 26.316 30.204 ;
     RECT  26.334 30.179 26.388 30.204 ;
     RECT  26.406 30.179 26.46 30.204 ;
     RECT  26.478 30.179 26.532 30.204 ;
     RECT  26.55 30.179 26.604 30.204 ;
     RECT  26.622 30.179 26.676 30.204 ;
     RECT  26.694 30.179 26.748 30.204 ;
     RECT  26.766 30.179 26.82 30.204 ;
     RECT  26.838 30.179 26.892 30.204 ;
     RECT  26.91 30.179 26.964 30.204 ;
     RECT  26.982 30.179 27.036 30.204 ;
     RECT  27.054 30.179 27.108 30.204 ;
     RECT  27.126 30.179 27.18 30.204 ;
     RECT  27.198 30.179 27.252 30.204 ;
     RECT  27.27 30.179 27.324 30.204 ;
     RECT  27.342 30.179 27.396 30.204 ;
     RECT  27.414 30.179 27.468 30.204 ;
     RECT  27.486 30.179 27.54 30.204 ;
     RECT  27.558 30.179 27.612 30.204 ;
     RECT  27.63 30.179 27.684 30.204 ;
     RECT  27.702 30.179 27.756 30.204 ;
     RECT  27.774 30.179 27.828 30.204 ;
     RECT  27.846 30.179 27.9 30.204 ;
     RECT  27.918 30.179 27.972 30.204 ;
     RECT  27.99 30.179 28.044 30.204 ;
     RECT  28.062 30.179 28.116 30.204 ;
     RECT  28.134 30.179 28.188 30.204 ;
     RECT  28.206 30.179 28.26 30.204 ;
     RECT  28.278 30.179 28.332 30.204 ;
     RECT  28.35 30.179 28.404 30.204 ;
     RECT  28.422 30.179 28.476 30.204 ;
     RECT  28.494 30.179 28.548 30.204 ;
     RECT  28.566 30.179 28.62 30.204 ;
     RECT  28.638 30.179 28.692 30.204 ;
     RECT  28.71 30.179 28.764 30.204 ;
     RECT  28.782 30.179 28.836 30.204 ;
     RECT  28.854 30.179 28.908 30.204 ;
     RECT  28.926 30.179 28.98 30.204 ;
     RECT  28.998 30.179 29.052 30.204 ;
     RECT  29.07 30.179 29.124 30.204 ;
     RECT  29.142 30.179 29.196 30.204 ;
     RECT  29.214 30.179 29.268 30.204 ;
     RECT  29.286 30.179 29.34 30.204 ;
     RECT  29.358 30.179 29.412 30.204 ;
     RECT  29.43 30.179 29.484 30.204 ;
     RECT  29.502 30.179 29.556 30.204 ;
     RECT  29.574 30.179 29.628 30.204 ;
     RECT  29.646 30.179 29.7 30.204 ;
     RECT  29.718 30.179 29.772 30.204 ;
     RECT  29.79 30.179 29.844 30.204 ;
     RECT  29.862 30.179 29.916 30.204 ;
     RECT  29.934 30.179 29.988 30.204 ;
     RECT  30.006 30.179 30.06 30.204 ;
     RECT  30.078 30.179 30.132 30.204 ;
     RECT  30.15 30.179 30.204 30.204 ;
     RECT  30.222 30.179 30.276 30.204 ;
     RECT  30.294 30.179 30.348 30.204 ;
     RECT  30.366 30.179 30.42 30.204 ;
     RECT  30.438 30.179 30.492 30.204 ;
     RECT  30.51 30.179 30.564 30.204 ;
     RECT  30.582 30.179 30.636 30.204 ;
     RECT  30.654 30.179 30.708 30.204 ;
     RECT  30.726 30.179 30.78 30.204 ;
     RECT  30.798 30.179 30.852 30.204 ;
     RECT  30.87 30.179 30.924 30.204 ;
     RECT  30.942 30.179 30.996 30.204 ;
     RECT  31.014 30.179 31.068 30.204 ;
     RECT  31.086 30.179 31.14 30.204 ;
     RECT  31.158 30.179 31.212 30.204 ;
     RECT  31.23 30.179 31.284 30.204 ;
     RECT  31.302 30.179 31.356 30.204 ;
     RECT  31.374 30.179 31.428 30.204 ;
     RECT  31.446 30.179 31.5 30.204 ;
     RECT  31.518 30.179 31.572 30.204 ;
     RECT  31.59 30.179 31.644 30.204 ;
     RECT  31.662 30.179 31.716 30.204 ;
     RECT  31.734 30.179 31.788 30.204 ;
     RECT  31.806 30.179 31.86 30.204 ;
     RECT  31.878 30.179 31.932 30.204 ;
     RECT  31.95 30.179 32.004 30.204 ;
     RECT  32.022 30.179 32.076 30.204 ;
     RECT  32.094 30.179 32.148 30.204 ;
     RECT  32.166 30.179 32.22 30.204 ;
     RECT  32.238 30.179 32.292 30.204 ;
     RECT  32.31 30.179 32.364 30.204 ;
     RECT  32.382 30.179 32.436 30.204 ;
     RECT  32.454 30.179 32.508 30.204 ;
     RECT  32.526 30.179 32.58 30.204 ;
     RECT  32.598 30.179 32.652 30.204 ;
     RECT  32.67 30.179 32.724 30.204 ;
     RECT  32.742 30.179 32.796 30.204 ;
     RECT  32.814 30.179 32.868 30.204 ;
     RECT  32.886 30.179 32.94 30.204 ;
     RECT  32.958 30.179 33.012 30.204 ;
     RECT  33.03 30.179 33.084 30.204 ;
    LAYER M4 ;
     RECT  2.408 2.148 2.512 27.552 ;
     RECT  2.512 2.418 2.6 27.552 ;
     RECT  2.6 2.418 2.704 27.822 ;
     RECT  5.108 2.148 5.212 27.552 ;
     RECT  5.212 2.418 5.3 27.552 ;
     RECT  5.3 2.418 5.404 27.822 ;
     RECT  7.808 2.148 7.912 27.552 ;
     RECT  7.912 2.418 8 27.552 ;
     RECT  8 2.418 8.104 27.822 ;
     RECT  10.508 2.148 10.612 27.552 ;
     RECT  10.612 2.418 10.7 27.552 ;
     RECT  10.7 2.418 10.804 27.822 ;
     RECT  13.208 2.148 13.312 27.552 ;
     RECT  13.312 2.418 13.4 27.552 ;
     RECT  13.4 2.418 13.504 27.822 ;
     RECT  15.908 2.148 16.012 27.552 ;
     RECT  16.012 2.418 16.1 27.552 ;
     RECT  16.1 2.418 16.204 27.822 ;
     RECT  18.608 2.148 18.712 27.552 ;
     RECT  18.712 2.418 18.8 27.552 ;
     RECT  18.8 2.418 18.904 27.822 ;
     RECT  21.308 2.148 21.412 27.552 ;
     RECT  21.412 2.418 21.5 27.552 ;
     RECT  21.5 2.418 21.604 27.822 ;
     RECT  24.008 2.148 24.112 27.552 ;
     RECT  24.112 2.418 24.2 27.552 ;
     RECT  24.2 2.418 24.304 27.822 ;
     RECT  24.304 26.784 25.369 26.808 ;
     RECT  25.369 26.784 25.621 27.384 ;
     RECT  25.621 26.736 25.909 27.384 ;
     RECT  25.729 25.632 26.125 25.656 ;
     RECT  25.909 26.736 26.125 27.624 ;
     RECT  25.765 30.096 26.269 30.12 ;
     RECT  26.269 30.096 26.417 30.168 ;
     RECT  26.125 25.248 26.708 27.624 ;
     RECT  26.708 2.148 26.812 27.624 ;
     RECT  26.812 2.418 26.9 27.624 ;
     RECT  26.9 2.418 27.004 27.822 ;
     RECT  26.417 30.096 27.209 30.12 ;
     RECT  27.004 21.936 27.533 27.822 ;
     RECT  27.533 21.936 28.145 26.904 ;
     RECT  28.145 23.808 28.825 26.904 ;
     RECT  27.925 27.984 28.825 28.008 ;
     RECT  28.897 0.48 28.969 0.504 ;
     RECT  28.789 30.144 29.009 30.168 ;
     RECT  28.145 21.936 29.016 22.728 ;
     RECT  28.825 23.808 29.113 28.008 ;
     RECT  29.016 21.648 29.125 22.728 ;
     RECT  29.113 23.808 29.125 28.152 ;
     RECT  28.969 0.384 29.149 0.504 ;
     RECT  29.149 0.384 29.185 0.552 ;
     RECT  29.185 0.384 29.221 1.128 ;
     RECT  29.005 2.256 29.408 2.28 ;
     RECT  28.861 3.408 29.408 3.432 ;
     RECT  28.261 6.24 29.408 6.264 ;
     RECT  29.125 21.648 29.408 28.152 ;
     RECT  29.408 2.148 29.437 28.152 ;
     RECT  29.437 2.148 29.704 28.536 ;
     RECT  29.221 0.192 29.725 1.128 ;
     RECT  29.704 2.148 29.725 2.856 ;
     RECT  29.725 0.192 30.131 2.856 ;
     RECT  30.131 0.192 30.265 1.128 ;
     RECT  30.131 2.256 30.419 2.856 ;
     RECT  30.265 0.096 30.481 1.128 ;
     RECT  29.704 21.936 30.481 28.536 ;
     RECT  30.277 29.856 30.481 30.072 ;
     RECT  30.481 21.936 30.611 30.072 ;
     RECT  29.704 3.936 30.707 3.96 ;
     RECT  30.611 29.04 30.737 30.072 ;
     RECT  30.419 2.832 30.841 2.856 ;
     RECT  30.611 21.936 30.853 27.912 ;
     RECT  29.704 5.04 30.877 5.112 ;
     RECT  30.737 29.904 30.913 30.072 ;
     RECT  30.841 2.832 31.091 3.432 ;
     RECT  30.913 29.904 31.091 30.168 ;
     RECT  30.853 21.216 31.141 27.912 ;
     RECT  30.481 0.048 31.187 1.128 ;
     RECT  31.141 21.12 31.189 27.912 ;
     RECT  31.091 30 31.235 30.168 ;
     RECT  31.189 20.736 31.273 27.912 ;
     RECT  30.877 4.512 31.58 5.112 ;
     RECT  31.273 20.448 31.621 27.912 ;
     RECT  31.091 2.832 31.669 3 ;
     RECT  31.621 20.448 31.717 27.96 ;
     RECT  31.717 20.448 31.813 28.248 ;
     RECT  31.669 2.256 31.921 3 ;
     RECT  31.813 20.448 31.993 28.344 ;
     RECT  31.993 20.448 32.105 28.968 ;
     RECT  31.921 1.92 32.108 3 ;
     RECT  31.58 4.512 32.108 5.928 ;
     RECT  30.853 15.504 32.108 15.528 ;
     RECT  32.105 20.448 32.108 28.488 ;
     RECT  31.235 30.048 32.147 30.168 ;
     RECT  32.108 1.92 32.404 28.488 ;
     RECT  32.404 1.92 32.435 1.944 ;
     RECT  32.147 30.144 32.465 30.168 ;
     RECT  32.404 17.616 32.627 17.64 ;
     RECT  32.404 21.12 32.675 28.488 ;
     RECT  32.404 5.664 32.819 5.688 ;
     RECT  32.785 1.728 33.011 1.752 ;
     RECT  32.675 21.12 33.059 22.248 ;
     RECT  31.187 0.048 33.308 0.552 ;
     RECT  33.397 5.088 33.481 5.112 ;
     RECT  33.308 0.048 33.581 1.704 ;
     RECT  33.059 21.12 33.581 22.152 ;
     RECT  32.675 23.568 33.683 28.488 ;
     RECT  33.581 0.096 34.189 1.704 ;
     RECT  34.189 0.096 34.265 1.992 ;
     RECT  34.265 1.68 34.355 1.992 ;
     RECT  33.581 21.264 34.441 22.152 ;
     RECT  34.355 1.728 34.501 1.992 ;
     RECT  34.549 5.568 34.657 5.592 ;
     RECT  34.265 0.096 34.661 0.648 ;
     RECT  32.404 7.872 34.685 7.896 ;
     RECT  34.501 1.728 34.808 2.328 ;
     RECT  34.513 3.936 34.808 3.96 ;
     RECT  34.657 5.04 34.808 5.592 ;
     RECT  34.685 7.872 34.808 8.568 ;
     RECT  32.404 15.504 34.808 15.528 ;
     RECT  34.441 21.264 34.808 22.824 ;
     RECT  33.683 24.048 34.808 28.488 ;
     RECT  34.808 1.728 35.104 28.488 ;
     RECT  35.104 21.696 35.201 28.488 ;
     RECT  35.201 21.696 35.219 28.248 ;
     RECT  35.104 15.504 35.245 16.008 ;
     RECT  35.104 11.424 35.315 11.976 ;
     RECT  35.104 13.104 35.315 13.368 ;
     RECT  35.315 13.344 35.353 13.368 ;
     RECT  35.219 21.696 35.363 23.352 ;
     RECT  35.219 25.056 35.389 28.248 ;
     RECT  35.363 21.696 35.497 22.824 ;
     RECT  35.104 1.728 35.507 2.28 ;
     RECT  35.389 25.44 35.597 28.248 ;
     RECT  34.661 0.192 35.603 0.648 ;
     RECT  35.603 0.528 35.629 0.648 ;
     RECT  35.507 1.728 35.629 1.752 ;
     RECT  35.497 21.696 35.813 22.056 ;
     RECT  35.629 0.528 35.849 1.752 ;
     RECT  35.813 21.888 35.885 22.056 ;
     RECT  35.597 25.968 35.885 28.248 ;
     RECT  35.315 11.952 35.987 11.976 ;
     RECT  35.885 25.968 35.993 28.2 ;
     RECT  35.104 4.992 36.083 5.112 ;
     RECT  35.993 25.968 36.137 26.664 ;
     RECT  35.993 27.648 36.137 28.2 ;
     RECT  36.137 26.208 36.173 26.664 ;
     RECT  36.083 4.992 36.179 5.016 ;
     RECT  36.137 28.176 36.245 28.2 ;
     RECT  35.104 3.936 36.349 3.96 ;
     RECT  36.173 26.208 36.533 26.28 ;
     RECT  35.849 0.528 36.745 1.128 ;
     RECT  36.745 0.48 36.851 1.128 ;
     RECT  36.851 0.48 36.853 0.552 ;
     RECT  36.853 0.432 36.925 0.552 ;
     RECT  36.901 1.728 37.001 1.752 ;
     RECT  35.245 15.504 37.249 15.528 ;
     RECT  36.925 0.384 37.429 0.552 ;
     RECT  36.349 3.696 37.508 3.96 ;
     RECT  37.357 6.864 37.508 6.888 ;
     RECT  36.457 8.544 37.508 8.568 ;
     RECT  37.249 15.264 37.508 15.528 ;
     RECT  35.885 21.888 37.508 21.912 ;
     RECT  36.533 26.208 37.508 26.232 ;
     RECT  37.508 2.148 37.612 27.552 ;
     RECT  37.612 2.418 37.7 27.552 ;
     RECT  37.429 0.336 37.765 0.552 ;
     RECT  37.7 2.418 37.804 27.822 ;
     RECT  37.765 0.096 37.916 0.552 ;
     RECT  37.916 0.096 38.003 1.128 ;
     RECT  38.003 0.096 38.195 0.552 ;
     RECT  38.195 0.096 38.297 0.12 ;
     RECT  37.804 15.264 40.208 15.528 ;
     RECT  40.208 2.148 40.312 27.552 ;
     RECT  40.312 2.418 40.4 27.552 ;
     RECT  40.4 2.418 40.504 27.822 ;
     RECT  40.504 15.264 42.908 15.528 ;
     RECT  42.908 2.148 43.012 27.552 ;
     RECT  43.012 2.418 43.1 27.552 ;
     RECT  43.1 2.418 43.204 27.822 ;
     RECT  43.204 15.264 45.608 15.528 ;
     RECT  45.608 2.148 45.712 27.552 ;
     RECT  45.712 2.418 45.8 27.552 ;
     RECT  45.8 2.418 45.904 27.822 ;
     RECT  45.904 15.168 46.793 15.528 ;
     RECT  46.793 15.264 48.308 15.528 ;
     RECT  48.308 2.148 48.412 27.552 ;
     RECT  48.412 2.418 48.5 27.552 ;
     RECT  48.5 2.418 48.604 27.822 ;
     RECT  48.604 15.264 51.008 15.528 ;
     RECT  51.008 2.148 51.112 27.552 ;
     RECT  51.112 2.418 51.2 27.552 ;
     RECT  51.2 2.418 51.304 27.822 ;
     RECT  51.304 15.264 53.708 15.528 ;
     RECT  53.708 2.148 53.812 27.552 ;
     RECT  53.812 2.418 53.9 27.552 ;
     RECT  53.9 2.418 54.004 27.822 ;
     RECT  54.004 15.168 54.749 15.528 ;
     RECT  54.749 15.264 56.408 15.528 ;
     RECT  56.408 2.148 56.512 27.552 ;
     RECT  56.512 2.418 56.6 27.552 ;
     RECT  56.6 2.418 56.704 27.822 ;
     RECT  56.704 15.264 59.108 15.528 ;
     RECT  59.108 2.148 59.212 27.552 ;
     RECT  59.212 2.418 59.3 27.552 ;
     RECT  59.3 2.418 59.404 27.822 ;
     RECT  59.404 15.264 61.808 15.528 ;
     RECT  61.808 2.148 61.912 27.552 ;
     RECT  61.912 2.418 62 27.552 ;
     RECT  62 2.418 62.104 27.822 ;
     RECT  62.104 15.168 62.741 15.528 ;
     RECT  62.741 15.312 64.692 15.336 ;
     RECT  62.741 15.336 64.716 15.408 ;
     RECT  62.741 15.408 64.692 15.432 ;
    LAYER M5 ;
     RECT  29.16 0.016 29.232 0.084 ;
     RECT  29.256 0.016 29.328 0.084 ;
     RECT  29.352 0.016 29.424 0.084 ;
     RECT  29.448 0.016 29.52 0.084 ;
     RECT  29.544 0.016 29.616 0.084 ;
     RECT  29.64 0.016 29.712 0.084 ;
     RECT  29.736 0.016 29.808 0.084 ;
     RECT  29.832 0.016 29.904 0.084 ;
     RECT  29.928 0.016 30 0.084 ;
     RECT  30.024 0.016 30.096 0.084 ;
     RECT  30.12 0.016 30.192 0.084 ;
     RECT  30.216 0.016 30.288 0.084 ;
     RECT  30.312 0.016 30.384 0.084 ;
     RECT  30.408 0.016 30.48 0.084 ;
     RECT  30.504 0.016 30.576 0.084 ;
     RECT  30.6 0.016 30.672 0.084 ;
     RECT  30.696 0.016 30.768 0.084 ;
     RECT  30.792 0.016 30.864 0.084 ;
     RECT  30.888 0.016 30.96 0.084 ;
     RECT  30.984 0.016 31.056 0.084 ;
     RECT  31.08 0.016 31.152 0.084 ;
     RECT  31.176 0.016 31.248 0.084 ;
     RECT  31.272 0.016 31.344 0.084 ;
     RECT  31.368 0.016 31.44 0.084 ;
     RECT  31.464 0.016 31.536 0.084 ;
     RECT  31.56 0.016 31.632 0.084 ;
     RECT  31.656 0.016 31.728 0.084 ;
     RECT  31.752 0.016 31.824 0.084 ;
     RECT  31.848 0.016 31.92 0.084 ;
     RECT  31.944 0.016 32.016 0.084 ;
     RECT  32.04 0.016 32.112 0.084 ;
     RECT  32.136 0.016 32.208 0.084 ;
     RECT  32.232 0.016 32.304 0.084 ;
     RECT  32.328 0.016 32.4 0.084 ;
     RECT  32.424 0.016 32.496 0.084 ;
     RECT  32.52 0.016 32.592 0.084 ;
     RECT  32.616 0.016 32.688 0.084 ;
     RECT  32.712 0.016 32.784 0.084 ;
     RECT  32.808 0.016 32.88 0.084 ;
     RECT  32.904 0.016 32.976 0.084 ;
     RECT  33 0.016 33.072 0.084 ;
     RECT  33.096 0.016 33.168 0.084 ;
     RECT  33.192 0.016 33.264 0.084 ;
     RECT  33.288 0.016 33.36 0.084 ;
     RECT  33.384 0.016 33.456 0.084 ;
     RECT  33.48 0.016 33.552 0.084 ;
     RECT  33.576 0.016 33.648 0.084 ;
     RECT  33.672 0.016 33.744 0.084 ;
     RECT  33.768 0.016 33.84 0.084 ;
     RECT  33.864 0.016 33.936 0.084 ;
     RECT  33.96 0.016 34.032 0.084 ;
     RECT  34.056 0.016 34.128 0.084 ;
     RECT  34.152 0.016 34.224 0.084 ;
     RECT  34.248 0.016 34.32 0.084 ;
     RECT  34.344 0.016 34.416 0.084 ;
     RECT  34.44 0.016 34.512 0.084 ;
     RECT  34.536 0.016 34.608 0.084 ;
     RECT  34.632 0.016 34.704 0.084 ;
     RECT  34.728 0.016 34.8 0.084 ;
     RECT  34.824 0.016 34.896 0.084 ;
     RECT  34.92 0.016 34.992 0.084 ;
     RECT  35.016 0.016 35.088 0.084 ;
     RECT  35.112 0.016 35.184 0.084 ;
     RECT  35.208 0.016 35.28 0.084 ;
     RECT  35.304 0.016 35.376 0.084 ;
     RECT  35.4 0.016 35.472 0.084 ;
     RECT  35.496 0.016 35.568 0.084 ;
     RECT  35.592 0.016 35.664 0.084 ;
     RECT  35.688 0.016 35.76 0.084 ;
     RECT  35.784 0.016 35.856 0.084 ;
     RECT  35.88 0.016 35.952 0.084 ;
     RECT  35.976 0.016 36.048 0.084 ;
     RECT  36.072 0.016 36.144 0.084 ;
     RECT  36.168 0.016 36.24 0.084 ;
     RECT  36.264 0.016 36.336 0.084 ;
     RECT  36.36 0.016 36.432 0.084 ;
     RECT  36.456 0.016 36.528 0.084 ;
     RECT  36.552 0.016 36.624 0.084 ;
     RECT  36.648 0.016 36.72 0.084 ;
     RECT  36.744 0.016 36.816 0.084 ;
     RECT  36.84 0.016 36.912 0.084 ;
     RECT  36.936 0.016 37.008 0.084 ;
     RECT  37.032 0.016 37.104 0.084 ;
     RECT  37.128 0.016 37.2 0.084 ;
     RECT  37.224 0.016 37.296 0.084 ;
     RECT  37.32 0.016 37.392 0.084 ;
     RECT  37.416 0.016 37.488 0.084 ;
     RECT  37.512 0.016 37.584 0.084 ;
     RECT  37.608 0.016 37.68 0.084 ;
     RECT  37.704 0.016 37.776 0.084 ;
     RECT  37.8 0.016 37.872 0.084 ;
     RECT  37.896 0.016 37.968 0.084 ;
     RECT  37.992 0.016 38.064 0.084 ;
     RECT  38.088 0.016 38.16 0.084 ;
     RECT  38.184 0.016 38.256 0.084 ;
     RECT  29.136 0.084 38.28 0.131 ;
     RECT  29.136 0.131 38.184 0.563 ;
     RECT  29.136 0.563 37.992 1.139 ;
     RECT  34.32 1.139 37.416 1.715 ;
     RECT  29.136 1.139 33 1.763 ;
     RECT  34.512 1.715 37.416 2.137 ;
     RECT  2.4 2.137 2.52 2.151 ;
     RECT  5.1 2.137 5.22 2.151 ;
     RECT  7.8 2.137 7.92 2.151 ;
     RECT  10.5 2.137 10.62 2.151 ;
     RECT  13.2 2.137 13.32 2.151 ;
     RECT  15.9 2.137 16.02 2.151 ;
     RECT  18.6 2.137 18.72 2.151 ;
     RECT  21.3 2.137 21.42 2.151 ;
     RECT  24 2.137 24.12 2.151 ;
     RECT  26.7 2.137 26.82 2.151 ;
     RECT  34.512 2.137 37.62 2.151 ;
     RECT  40.2 2.137 40.32 2.151 ;
     RECT  42.9 2.137 43.02 2.151 ;
     RECT  45.6 2.137 45.72 2.151 ;
     RECT  48.3 2.137 48.42 2.151 ;
     RECT  51 2.137 51.12 2.151 ;
     RECT  53.7 2.137 53.82 2.151 ;
     RECT  56.4 2.137 56.52 2.151 ;
     RECT  59.1 2.137 59.22 2.151 ;
     RECT  61.8 2.137 61.92 2.151 ;
     RECT  29.136 1.763 32.808 2.291 ;
     RECT  29.232 2.291 32.808 3.443 ;
     RECT  29.4 3.443 32.808 5.077 ;
     RECT  34.512 2.151 37.812 8.579 ;
     RECT  34.512 8.579 35.976 11.987 ;
     RECT  29.4 5.077 33.432 21.541 ;
     RECT  34.512 11.987 35.448 21.541 ;
     RECT  28.272 6.229 28.296 21.637 ;
     RECT  29.4 21.541 35.448 21.637 ;
     RECT  28.272 21.637 35.448 21.779 ;
     RECT  26.7 2.151 27.012 22.597 ;
     RECT  28.272 21.779 33.432 22.597 ;
     RECT  34.512 21.779 35.448 22.835 ;
     RECT  26.7 22.597 33.432 23.557 ;
     RECT  26.7 23.557 33.672 24.755 ;
     RECT  26.7 24.755 33.432 25.139 ;
     RECT  34.8 22.835 35.352 25.475 ;
     RECT  28.272 25.139 33.432 25.715 ;
     RECT  29.136 25.715 33.432 25.859 ;
     RECT  29.4 25.859 33.432 26.627 ;
     RECT  25.632 26.725 25.656 27.395 ;
     RECT  34.8 25.475 35.112 27.589 ;
     RECT  2.4 2.151 2.712 27.819 ;
     RECT  5.1 2.151 5.412 27.819 ;
     RECT  7.8 2.151 8.112 27.819 ;
     RECT  10.5 2.151 10.812 27.819 ;
     RECT  13.2 2.151 13.512 27.819 ;
     RECT  15.9 2.151 16.212 27.819 ;
     RECT  18.6 2.151 18.912 27.819 ;
     RECT  21.3 2.151 21.612 27.819 ;
     RECT  24 2.151 24.312 27.819 ;
     RECT  26.7 25.139 27.012 27.819 ;
     RECT  29.4 26.627 33.096 27.819 ;
     RECT  34.8 27.589 35.592 27.819 ;
     RECT  37.5 8.579 37.812 27.819 ;
     RECT  40.2 2.151 40.512 27.819 ;
     RECT  42.9 2.151 43.212 27.819 ;
     RECT  45.6 2.151 45.912 27.819 ;
     RECT  48.3 2.151 48.612 27.819 ;
     RECT  51 2.151 51.312 27.819 ;
     RECT  53.7 2.151 54.012 27.819 ;
     RECT  56.4 2.151 56.712 27.819 ;
     RECT  59.1 2.151 59.412 27.819 ;
     RECT  61.8 2.151 62.112 27.819 ;
     RECT  2.592 27.819 2.712 27.833 ;
     RECT  5.292 27.819 5.412 27.833 ;
     RECT  7.992 27.819 8.112 27.833 ;
     RECT  10.692 27.819 10.812 27.833 ;
     RECT  13.392 27.819 13.512 27.833 ;
     RECT  16.092 27.819 16.212 27.833 ;
     RECT  18.792 27.819 18.912 27.833 ;
     RECT  21.492 27.819 21.612 27.833 ;
     RECT  24.192 27.819 24.312 27.833 ;
     RECT  26.892 27.819 27.012 27.833 ;
     RECT  34.992 27.819 35.592 27.833 ;
     RECT  37.692 27.819 37.812 27.833 ;
     RECT  40.392 27.819 40.512 27.833 ;
     RECT  43.092 27.819 43.212 27.833 ;
     RECT  45.792 27.819 45.912 27.833 ;
     RECT  48.492 27.819 48.612 27.833 ;
     RECT  51.192 27.819 51.312 27.833 ;
     RECT  53.892 27.819 54.012 27.833 ;
     RECT  56.592 27.819 56.712 27.833 ;
     RECT  59.292 27.819 59.412 27.833 ;
     RECT  61.992 27.819 62.112 27.833 ;
     RECT  29.52 27.819 33.096 28.019 ;
     RECT  29.52 28.019 32.52 30.132 ;
     RECT  29.544 30.132 29.616 30.16 ;
     RECT  29.64 30.132 29.712 30.16 ;
     RECT  29.736 30.132 29.808 30.16 ;
     RECT  29.832 30.132 29.904 30.16 ;
     RECT  29.928 30.132 30 30.16 ;
     RECT  30.024 30.132 30.096 30.16 ;
     RECT  30.12 30.132 30.192 30.16 ;
     RECT  30.216 30.132 30.288 30.16 ;
     RECT  30.312 30.132 30.384 30.16 ;
     RECT  30.408 30.132 30.48 30.16 ;
     RECT  30.504 30.132 30.576 30.16 ;
     RECT  30.6 30.132 30.672 30.16 ;
     RECT  30.696 30.132 30.768 30.16 ;
     RECT  30.792 30.132 30.864 30.16 ;
     RECT  30.888 30.132 30.96 30.16 ;
     RECT  30.984 30.132 31.056 30.16 ;
     RECT  31.08 30.132 31.152 30.16 ;
     RECT  31.176 30.132 31.248 30.16 ;
     RECT  31.272 30.132 31.344 30.16 ;
     RECT  31.368 30.132 31.44 30.16 ;
     RECT  31.464 30.132 31.536 30.16 ;
     RECT  31.56 30.132 31.632 30.16 ;
     RECT  31.656 30.132 31.728 30.16 ;
     RECT  31.752 30.132 31.824 30.16 ;
     RECT  31.848 30.132 31.92 30.16 ;
     RECT  31.944 30.132 32.016 30.16 ;
     RECT  32.04 30.132 32.112 30.16 ;
     RECT  32.136 30.132 32.208 30.16 ;
     RECT  32.232 30.132 32.304 30.16 ;
     RECT  32.328 30.132 32.4 30.16 ;
     RECT  32.424 30.132 32.496 30.16 ;
     RECT  33 1.139 34.32 1.715 ;
     RECT  37.416 1.139 37.812 2.137 ;
     RECT  33 1.715 34.512 1.763 ;
     RECT  37.62 2.137 37.812 2.151 ;
     RECT  33.432 5.077 34.512 21.541 ;
     RECT  27.012 6.229 28.272 22.597 ;
     RECT  28.296 6.229 29.4 21.637 ;
     RECT  35.976 8.579 37.5 11.987 ;
     RECT  33.432 21.779 34.512 22.835 ;
     RECT  33.432 22.835 34.8 23.557 ;
     RECT  33.672 23.557 34.8 24.755 ;
     RECT  33.432 24.755 34.8 26.627 ;
     RECT  27.012 25.139 28.272 25.715 ;
     RECT  24.312 26.725 25.632 27.395 ;
     RECT  25.656 26.725 26.7 27.395 ;
  END
END qfd_rlyh_128_NS_65x30
END LIBRARY
